VERSION 5.7 ;
DIVIDERCHAR "/" ;
BUSBITCHARS "[]" ;

VERSION 5.7 ;

BUSBITCHARS "[]" ;
DIVIDERCHAR "/" ;

UNITS
  TIME NANOSECONDS 1 ;
  CAPACITANCE PICOFARADS 1 ;
  RESISTANCE OHMS 1 ;
  DATABASE MICRONS 1000 ;
END UNITS

MANUFACTURINGGRID 0.005 ;

PROPERTYDEFINITIONS
  LAYER LEF58_TYPE STRING ;
END PROPERTYDEFINITIONS

# High density, single height
SITE obssite
  SYMMETRY Y ;
  CLASS CORE ;
  SIZE 0.36 BY 6.12 ;
END obssite


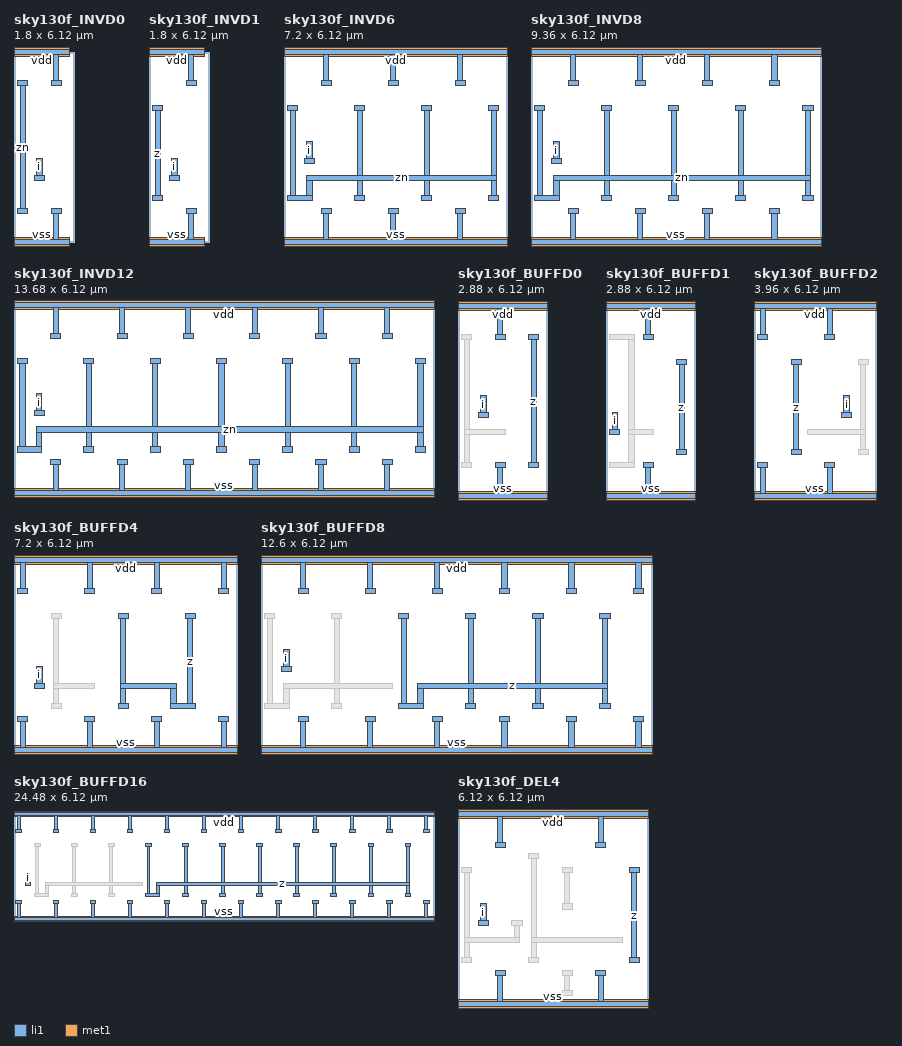
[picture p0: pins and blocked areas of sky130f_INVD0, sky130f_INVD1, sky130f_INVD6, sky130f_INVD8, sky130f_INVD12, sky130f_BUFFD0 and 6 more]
MACRO sky130f_INVD0
  CLASS CORE ;
  FOREIGN sky130f_INVD0 ;
  ORIGIN 0.000 0.000 ;
  SIZE 1.800 BY 6.120 ;
  SYMMETRY X Y R90 ;
  SITE obssite ;
  PIN i
    DIRECTION INPUT ;
    USE SIGNAL ;
    ANTENNAGATEAREA 0.145500 ;
    PORT
      LAYER li1 ;
        RECT 0.655 1.980 0.985 2.150 ;
        RECT 0.735 2.150 0.905 2.690 ;
    END
  END i
  PIN vdd
    DIRECTION INOUT ;
    USE POWER ;
    SHAPE ABUTMENT ;
    PORT
      LAYER li1 ;
        RECT 1.195 5.030 1.525 5.200 ;
        RECT 1.275 5.200 1.445 6.035 ;
        RECT 0.000 6.035 1.800 6.205 ;
      LAYER met1 ;
        RECT 0.000 5.985 1.800 6.255 ;
    END
  END vdd
  PIN vss
    DIRECTION INOUT ;
    USE GROUND ;
    SHAPE ABUTMENT ;
    PORT
      LAYER li1 ;
        RECT 0.000 -0.085 1.800 0.085 ;
        RECT 1.275 0.085 1.445 0.920 ;
        RECT 1.195 0.920 1.525 1.090 ;
      LAYER met1 ;
        RECT 0.000 -0.135 1.800 0.135 ;
    END
  END vss
  PIN zn
    DIRECTION OUTPUT ;
    USE SIGNAL ;
    ANTENNADIFFAREA 0.591700 ;
    PORT
      LAYER li1 ;
        RECT 0.115 0.920 0.445 1.090 ;
        RECT 0.195 1.090 0.365 5.030 ;
        RECT 0.115 5.030 0.445 5.200 ;
    END
  END zn
END sky130f_INVD0

MACRO sky130f_INVD1
  CLASS CORE ;
  FOREIGN sky130f_INVD1 ;
  ORIGIN 0.000 0.000 ;
  SIZE 1.800 BY 6.120 ;
  SYMMETRY X Y R90 ;
  SITE obssite ;
  PIN z
    DIRECTION OUTPUT ;
    USE SIGNAL ;
    ANTENNADIFFAREA 1.098000 ;
    PORT
      LAYER li1 ;
        RECT 0.115 1.330 0.445 1.500 ;
        RECT 0.195 1.500 0.365 4.220 ;
        RECT 0.115 4.220 0.445 4.390 ;
    END
  END z
  PIN vdd
    DIRECTION INOUT ;
    USE POWER ;
    SHAPE ABUTMENT ;
    PORT
      LAYER li1 ;
        RECT 1.195 5.030 1.525 5.200 ;
        RECT 1.275 5.200 1.445 6.035 ;
        RECT 0.000 6.035 1.800 6.205 ;
      LAYER met1 ;
        RECT 0.000 5.985 1.800 6.255 ;
    END
  END vdd
  PIN vss
    DIRECTION INOUT ;
    USE GROUND ;
    SHAPE ABUTMENT ;
    PORT
      LAYER li1 ;
        RECT 0.000 -0.085 1.800 0.085 ;
        RECT 1.275 0.085 1.445 0.920 ;
        RECT 1.195 0.920 1.525 1.090 ;
      LAYER met1 ;
        RECT 0.000 -0.135 1.800 0.135 ;
    END
  END vss
  PIN i
    DIRECTION INPUT ;
    USE SIGNAL ;
    ANTENNAGATEAREA 0.270000 ;
    PORT
      LAYER li1 ;
        RECT 0.655 1.980 0.985 2.150 ;
        RECT 0.735 2.150 0.905 2.690 ;
    END
  END i
END sky130f_INVD1

MACRO sky130f_INVD6
  CLASS CORE ;
  FOREIGN sky130f_INVD6 ;
  ORIGIN 0.000 0.000 ;
  SIZE 7.200 BY 6.120 ;
  SYMMETRY X Y R90 ;
  SITE obssite ;
  PIN i
    DIRECTION INPUT ;
    USE SIGNAL ;
    ANTENNAGATEAREA 1.620000 ;
    PORT
      LAYER li1 ;
        RECT 0.655 2.520 0.985 2.690 ;
        RECT 0.735 2.690 0.905 3.230 ;
    END
  END i
  PIN vdd
    DIRECTION INOUT ;
    USE POWER ;
    SHAPE ABUTMENT ;
    PORT
      LAYER li1 ;
        RECT 1.195 5.030 1.525 5.200 ;
        RECT 3.355 5.030 3.685 5.200 ;
        RECT 5.515 5.030 5.845 5.200 ;
        RECT 1.275 5.200 1.445 6.035 ;
        RECT 3.435 5.200 3.605 6.035 ;
        RECT 5.595 5.200 5.765 6.035 ;
        RECT 0.000 6.035 7.200 6.205 ;
      LAYER met1 ;
        RECT 0.000 5.985 7.200 6.255 ;
    END
  END vdd
  PIN vss
    DIRECTION INOUT ;
    USE GROUND ;
    SHAPE ABUTMENT ;
    PORT
      LAYER li1 ;
        RECT 0.000 -0.085 7.200 0.085 ;
        RECT 1.275 0.085 1.445 0.920 ;
        RECT 3.435 0.085 3.605 0.920 ;
        RECT 5.595 0.085 5.765 0.920 ;
        RECT 1.195 0.920 1.525 1.090 ;
        RECT 3.355 0.920 3.685 1.090 ;
        RECT 5.515 0.920 5.845 1.090 ;
      LAYER met1 ;
        RECT 0.000 -0.135 7.200 0.135 ;
    END
  END vss
  PIN zn
    DIRECTION OUTPUT ;
    USE SIGNAL ;
    ANTENNADIFFAREA 5.544000 ;
    PORT
      LAYER li1 ;
        RECT 0.115 1.330 0.905 1.500 ;
        RECT 2.275 1.330 2.605 1.500 ;
        RECT 4.435 1.330 4.765 1.500 ;
        RECT 6.595 1.330 6.925 1.500 ;
        RECT 0.195 1.500 0.365 4.220 ;
        RECT 0.735 1.500 0.905 1.980 ;
        RECT 2.355 1.500 2.525 1.980 ;
        RECT 4.515 1.500 4.685 1.980 ;
        RECT 6.675 1.500 6.845 1.980 ;
        RECT 0.735 1.980 6.845 2.150 ;
        RECT 2.355 2.150 2.525 4.220 ;
        RECT 4.515 2.150 4.685 4.220 ;
        RECT 6.675 2.150 6.845 4.220 ;
        RECT 0.115 4.220 0.445 4.390 ;
        RECT 2.275 4.220 2.605 4.390 ;
        RECT 4.435 4.220 4.765 4.390 ;
        RECT 6.595 4.220 6.925 4.390 ;
    END
  END zn
END sky130f_INVD6

MACRO sky130f_INVD8
  CLASS CORE ;
  FOREIGN sky130f_INVD8 ;
  ORIGIN 0.000 0.000 ;
  SIZE 9.360 BY 6.120 ;
  SYMMETRY X Y R90 ;
  SITE obssite ;
  PIN i
    DIRECTION INPUT ;
    USE SIGNAL ;
    ANTENNAGATEAREA 2.160000 ;
    PORT
      LAYER li1 ;
        RECT 0.655 2.520 0.985 2.690 ;
        RECT 0.735 2.690 0.905 3.230 ;
    END
  END i
  PIN vdd
    DIRECTION INOUT ;
    USE POWER ;
    SHAPE ABUTMENT ;
    PORT
      LAYER li1 ;
        RECT 1.195 5.030 1.525 5.200 ;
        RECT 3.355 5.030 3.685 5.200 ;
        RECT 5.515 5.030 5.845 5.200 ;
        RECT 7.675 5.030 8.005 5.200 ;
        RECT 1.275 5.200 1.445 6.035 ;
        RECT 3.435 5.200 3.605 6.035 ;
        RECT 5.595 5.200 5.765 6.035 ;
        RECT 7.755 5.200 7.925 6.035 ;
        RECT 0.000 6.035 9.360 6.205 ;
      LAYER met1 ;
        RECT 0.000 5.985 9.360 6.255 ;
    END
  END vdd
  PIN vss
    DIRECTION INOUT ;
    USE GROUND ;
    SHAPE ABUTMENT ;
    PORT
      LAYER li1 ;
        RECT 0.000 -0.085 9.360 0.085 ;
        RECT 1.275 0.085 1.445 0.920 ;
        RECT 3.435 0.085 3.605 0.920 ;
        RECT 5.595 0.085 5.765 0.920 ;
        RECT 7.755 0.085 7.925 0.920 ;
        RECT 1.195 0.920 1.525 1.090 ;
        RECT 3.355 0.920 3.685 1.090 ;
        RECT 5.515 0.920 5.845 1.090 ;
        RECT 7.675 0.920 8.005 1.090 ;
      LAYER met1 ;
        RECT 0.000 -0.135 9.360 0.135 ;
    END
  END vss
  PIN zn
    DIRECTION OUTPUT ;
    USE SIGNAL ;
    ANTENNADIFFAREA 7.218000 ;
    PORT
      LAYER li1 ;
        RECT 0.115 1.330 0.905 1.500 ;
        RECT 2.275 1.330 2.605 1.500 ;
        RECT 4.435 1.330 4.765 1.500 ;
        RECT 6.595 1.330 6.925 1.500 ;
        RECT 8.755 1.330 9.085 1.500 ;
        RECT 0.195 1.500 0.365 4.220 ;
        RECT 0.735 1.500 0.905 1.980 ;
        RECT 2.355 1.500 2.525 1.980 ;
        RECT 4.515 1.500 4.685 1.980 ;
        RECT 6.675 1.500 6.845 1.980 ;
        RECT 8.835 1.500 9.005 1.980 ;
        RECT 0.735 1.980 9.005 2.150 ;
        RECT 2.355 2.150 2.525 4.220 ;
        RECT 4.515 2.150 4.685 4.220 ;
        RECT 6.675 2.150 6.845 4.220 ;
        RECT 8.835 2.150 9.005 4.220 ;
        RECT 0.115 4.220 0.445 4.390 ;
        RECT 2.275 4.220 2.605 4.390 ;
        RECT 4.435 4.220 4.765 4.390 ;
        RECT 6.595 4.220 6.925 4.390 ;
        RECT 8.755 4.220 9.085 4.390 ;
    END
  END zn
END sky130f_INVD8

MACRO sky130f_INVD12
  CLASS CORE ;
  FOREIGN sky130f_INVD12 ;
  ORIGIN 0.000 0.000 ;
  SIZE 13.680 BY 6.120 ;
  SYMMETRY X Y R90 ;
  SITE obssite ;
  PIN i
    DIRECTION INPUT ;
    USE SIGNAL ;
    ANTENNAGATEAREA 3.240000 ;
    PORT
      LAYER li1 ;
        RECT 0.655 2.520 0.985 2.690 ;
        RECT 0.735 2.690 0.905 3.230 ;
    END
  END i
  PIN vdd
    DIRECTION INOUT ;
    USE POWER ;
    SHAPE ABUTMENT ;
    PORT
      LAYER li1 ;
        RECT 1.195 5.030 1.525 5.200 ;
        RECT 3.355 5.030 3.685 5.200 ;
        RECT 5.515 5.030 5.845 5.200 ;
        RECT 7.675 5.030 8.005 5.200 ;
        RECT 9.835 5.030 10.165 5.200 ;
        RECT 11.995 5.030 12.325 5.200 ;
        RECT 1.275 5.200 1.445 6.035 ;
        RECT 3.435 5.200 3.605 6.035 ;
        RECT 5.595 5.200 5.765 6.035 ;
        RECT 7.755 5.200 7.925 6.035 ;
        RECT 9.915 5.200 10.085 6.035 ;
        RECT 12.075 5.200 12.245 6.035 ;
        RECT 0.000 6.035 13.680 6.205 ;
      LAYER met1 ;
        RECT 0.000 5.985 13.680 6.255 ;
    END
  END vdd
  PIN vss
    DIRECTION INOUT ;
    USE GROUND ;
    SHAPE ABUTMENT ;
    PORT
      LAYER li1 ;
        RECT 0.000 -0.085 13.680 0.085 ;
        RECT 1.275 0.085 1.445 0.920 ;
        RECT 3.435 0.085 3.605 0.920 ;
        RECT 5.595 0.085 5.765 0.920 ;
        RECT 7.755 0.085 7.925 0.920 ;
        RECT 9.915 0.085 10.085 0.920 ;
        RECT 12.075 0.085 12.245 0.920 ;
        RECT 1.195 0.920 1.525 1.090 ;
        RECT 3.355 0.920 3.685 1.090 ;
        RECT 5.515 0.920 5.845 1.090 ;
        RECT 7.675 0.920 8.005 1.090 ;
        RECT 9.835 0.920 10.165 1.090 ;
        RECT 11.995 0.920 12.325 1.090 ;
      LAYER met1 ;
        RECT 0.000 -0.135 13.680 0.135 ;
    END
  END vss
  PIN zn
    DIRECTION OUTPUT ;
    USE SIGNAL ;
    ANTENNADIFFAREA 10.566000 ;
    PORT
      LAYER li1 ;
        RECT 0.115 1.330 0.905 1.500 ;
        RECT 2.275 1.330 2.605 1.500 ;
        RECT 4.435 1.330 4.765 1.500 ;
        RECT 6.595 1.330 6.925 1.500 ;
        RECT 8.755 1.330 9.085 1.500 ;
        RECT 10.915 1.330 11.245 1.500 ;
        RECT 13.075 1.330 13.405 1.500 ;
        RECT 0.195 1.500 0.365 4.220 ;
        RECT 0.735 1.500 0.905 1.980 ;
        RECT 2.355 1.500 2.525 1.980 ;
        RECT 4.515 1.500 4.685 1.980 ;
        RECT 6.675 1.500 6.845 1.980 ;
        RECT 8.835 1.500 9.005 1.980 ;
        RECT 10.995 1.500 11.165 1.980 ;
        RECT 13.155 1.500 13.325 1.980 ;
        RECT 0.735 1.980 13.325 2.150 ;
        RECT 2.355 2.150 2.525 4.220 ;
        RECT 4.515 2.150 4.685 4.220 ;
        RECT 6.675 2.150 6.845 4.220 ;
        RECT 8.835 2.150 9.005 4.220 ;
        RECT 10.995 2.150 11.165 4.220 ;
        RECT 13.155 2.150 13.325 4.220 ;
        RECT 0.115 4.220 0.445 4.390 ;
        RECT 2.275 4.220 2.605 4.390 ;
        RECT 4.435 4.220 4.765 4.390 ;
        RECT 6.595 4.220 6.925 4.390 ;
        RECT 8.755 4.220 9.085 4.390 ;
        RECT 10.915 4.220 11.245 4.390 ;
        RECT 13.075 4.220 13.405 4.390 ;
    END
  END zn
END sky130f_INVD12

MACRO sky130f_BUFFD0
  CLASS CORE ;
  FOREIGN sky130f_BUFFD0 ;
  ORIGIN 0.000 0.000 ;
  SIZE 2.880 BY 6.120 ;
  SYMMETRY X Y R90 ;
  SITE obssite ;
  PIN i
    DIRECTION INPUT ;
    USE SIGNAL ;
    ANTENNAGATEAREA 0.126000 ;
    PORT
      LAYER li1 ;
        RECT 0.655 2.520 0.985 2.690 ;
        RECT 0.735 2.690 0.905 3.230 ;
    END
  END i
  PIN vdd
    DIRECTION INOUT ;
    USE POWER ;
    SHAPE ABUTMENT ;
    PORT
      LAYER li1 ;
        RECT 1.195 5.030 1.525 5.200 ;
        RECT 1.275 5.200 1.445 6.035 ;
        RECT 0.000 6.035 2.880 6.205 ;
      LAYER met1 ;
        RECT 0.000 5.985 2.880 6.255 ;
    END
  END vdd
  PIN vss
    DIRECTION INOUT ;
    USE GROUND ;
    SHAPE ABUTMENT ;
    PORT
      LAYER li1 ;
        RECT 0.000 -0.085 2.880 0.085 ;
        RECT 1.275 0.085 1.445 0.920 ;
        RECT 1.195 0.920 1.525 1.090 ;
      LAYER met1 ;
        RECT 0.000 -0.135 2.880 0.135 ;
    END
  END vss
  PIN z
    DIRECTION OUTPUT ;
    USE SIGNAL ;
    ANTENNADIFFAREA 0.582550 ;
    PORT
      LAYER li1 ;
        RECT 2.275 0.920 2.605 1.090 ;
        RECT 2.355 1.090 2.525 5.030 ;
        RECT 2.275 5.030 2.605 5.200 ;
    END
  END z
  OBS
    LAYER li1 ;
      RECT 0.115 0.920 0.445 1.090 ;
      RECT 0.195 1.090 0.365 1.980 ;
      RECT 0.195 1.980 1.525 2.150 ;
      RECT 0.195 2.150 0.365 5.030 ;
      RECT 0.115 5.030 0.445 5.200 ;
  END
END sky130f_BUFFD0

MACRO sky130f_BUFFD1
  CLASS CORE ;
  FOREIGN sky130f_BUFFD1 ;
  ORIGIN 0.000 0.000 ;
  SIZE 2.880 BY 6.120 ;
  SYMMETRY X Y R90 ;
  SITE obssite ;
  PIN i
    DIRECTION INPUT ;
    USE SIGNAL ;
    ANTENNAGATEAREA 0.145500 ;
    PORT
      LAYER li1 ;
        RECT 0.115 1.980 0.445 2.150 ;
        RECT 0.195 2.150 0.365 2.690 ;
    END
  END i
  PIN vdd
    DIRECTION INOUT ;
    USE POWER ;
    SHAPE ABUTMENT ;
    PORT
      LAYER li1 ;
        RECT 1.195 5.030 1.525 5.200 ;
        RECT 1.275 5.200 1.445 6.035 ;
        RECT 0.000 6.035 2.880 6.205 ;
      LAYER met1 ;
        RECT 0.000 5.985 2.880 6.255 ;
    END
  END vdd
  PIN vss
    DIRECTION INOUT ;
    USE GROUND ;
    SHAPE ABUTMENT ;
    PORT
      LAYER li1 ;
        RECT 0.000 -0.085 2.880 0.085 ;
        RECT 1.275 0.085 1.445 0.920 ;
        RECT 1.195 0.920 1.525 1.090 ;
      LAYER met1 ;
        RECT 0.000 -0.135 2.880 0.135 ;
    END
  END vss
  PIN z
    DIRECTION OUTPUT ;
    USE SIGNAL ;
    ANTENNADIFFAREA 1.098000 ;
    PORT
      LAYER li1 ;
        RECT 2.275 1.330 2.605 1.500 ;
        RECT 2.355 1.500 2.525 4.220 ;
        RECT 2.275 4.220 2.605 4.390 ;
    END
  END z
  OBS
    LAYER li1 ;
      RECT 0.115 0.920 0.905 1.090 ;
      RECT 0.735 1.090 0.905 1.980 ;
      RECT 0.735 1.980 1.525 2.150 ;
      RECT 0.735 2.150 0.905 5.030 ;
      RECT 0.115 5.030 0.905 5.200 ;
  END
END sky130f_BUFFD1

MACRO sky130f_BUFFD2
  CLASS CORE ;
  FOREIGN sky130f_BUFFD2 ;
  ORIGIN 0.000 0.000 ;
  SIZE 3.960 BY 6.120 ;
  SYMMETRY X Y R90 ;
  SITE obssite ;
  PIN i
    DIRECTION INPUT ;
    USE SIGNAL ;
    ANTENNAGATEAREA 0.270000 ;
    PORT
      LAYER li1 ;
        RECT 2.815 2.520 3.145 2.690 ;
        RECT 2.895 2.690 3.065 3.230 ;
    END
  END i
  PIN vdd
    DIRECTION INOUT ;
    USE POWER ;
    SHAPE ABUTMENT ;
    PORT
      LAYER li1 ;
        RECT 0.115 5.030 0.445 5.200 ;
        RECT 2.275 5.030 2.605 5.200 ;
        RECT 0.195 5.200 0.365 6.035 ;
        RECT 2.355 5.200 2.525 6.035 ;
        RECT 0.000 6.035 3.960 6.205 ;
      LAYER met1 ;
        RECT 0.000 5.985 3.960 6.255 ;
    END
  END vdd
  PIN vss
    DIRECTION INOUT ;
    USE GROUND ;
    SHAPE ABUTMENT ;
    PORT
      LAYER li1 ;
        RECT 0.000 -0.085 3.960 0.085 ;
        RECT 0.195 0.085 0.365 0.920 ;
        RECT 2.355 0.085 2.525 0.920 ;
        RECT 0.115 0.920 0.445 1.090 ;
        RECT 2.275 0.920 2.605 1.090 ;
      LAYER met1 ;
        RECT 0.000 -0.135 3.960 0.135 ;
    END
  END vss
  PIN z
    DIRECTION OUTPUT ;
    USE SIGNAL ;
    ANTENNADIFFAREA 1.674000 ;
    PORT
      LAYER li1 ;
        RECT 1.195 1.330 1.525 1.500 ;
        RECT 1.275 1.500 1.445 4.220 ;
        RECT 1.195 4.220 1.525 4.390 ;
    END
  END z
  OBS
    LAYER li1 ;
      RECT 3.355 1.330 3.685 1.500 ;
      RECT 3.435 1.500 3.605 1.980 ;
      RECT 1.735 1.980 3.605 2.150 ;
      RECT 3.435 2.150 3.605 4.220 ;
      RECT 3.355 4.220 3.685 4.390 ;
  END
END sky130f_BUFFD2

MACRO sky130f_BUFFD4
  CLASS CORE ;
  FOREIGN sky130f_BUFFD4 ;
  ORIGIN 0.000 0.000 ;
  SIZE 7.200 BY 6.120 ;
  SYMMETRY X Y R90 ;
  SITE obssite ;
  PIN i
    DIRECTION INPUT ;
    USE SIGNAL ;
    ANTENNAGATEAREA 0.540000 ;
    PORT
      LAYER li1 ;
        RECT 0.655 1.980 0.985 2.150 ;
        RECT 0.735 2.150 0.905 2.690 ;
    END
  END i
  PIN vdd
    DIRECTION INOUT ;
    USE POWER ;
    SHAPE ABUTMENT ;
    PORT
      LAYER li1 ;
        RECT 0.115 5.030 0.445 5.200 ;
        RECT 2.275 5.030 2.605 5.200 ;
        RECT 4.435 5.030 4.765 5.200 ;
        RECT 6.595 5.030 6.925 5.200 ;
        RECT 0.195 5.200 0.365 6.035 ;
        RECT 2.355 5.200 2.525 6.035 ;
        RECT 4.515 5.200 4.685 6.035 ;
        RECT 6.675 5.200 6.845 6.035 ;
        RECT 0.000 6.035 7.200 6.205 ;
      LAYER met1 ;
        RECT 0.000 5.985 7.200 6.255 ;
    END
  END vdd
  PIN vss
    DIRECTION INOUT ;
    USE GROUND ;
    SHAPE ABUTMENT ;
    PORT
      LAYER li1 ;
        RECT 0.000 -0.085 7.200 0.085 ;
        RECT 0.195 0.085 0.365 0.920 ;
        RECT 2.355 0.085 2.525 0.920 ;
        RECT 4.515 0.085 4.685 0.920 ;
        RECT 6.675 0.085 6.845 0.920 ;
        RECT 0.115 0.920 0.445 1.090 ;
        RECT 2.275 0.920 2.605 1.090 ;
        RECT 4.435 0.920 4.765 1.090 ;
        RECT 6.595 0.920 6.925 1.090 ;
      LAYER met1 ;
        RECT 0.000 -0.135 7.200 0.135 ;
    END
  END vss
  PIN z
    DIRECTION OUTPUT ;
    USE SIGNAL ;
    ANTENNADIFFAREA 3.348000 ;
    PORT
      LAYER li1 ;
        RECT 3.355 1.330 3.685 1.500 ;
        RECT 5.055 1.330 5.845 1.500 ;
        RECT 3.435 1.500 3.605 1.980 ;
        RECT 5.055 1.500 5.225 1.980 ;
        RECT 5.595 1.500 5.765 4.220 ;
        RECT 3.435 1.980 5.225 2.150 ;
        RECT 3.435 2.150 3.605 4.220 ;
        RECT 3.355 4.220 3.685 4.390 ;
        RECT 5.515 4.220 5.845 4.390 ;
    END
  END z
  OBS
    LAYER li1 ;
      RECT 1.195 1.330 1.525 1.500 ;
      RECT 1.275 1.500 1.445 1.980 ;
      RECT 1.275 1.980 2.605 2.150 ;
      RECT 1.275 2.150 1.445 4.220 ;
      RECT 1.195 4.220 1.525 4.390 ;
  END
END sky130f_BUFFD4

MACRO sky130f_BUFFD8
  CLASS CORE ;
  FOREIGN sky130f_BUFFD8 ;
  ORIGIN 0.000 0.000 ;
  SIZE 12.600 BY 6.120 ;
  SYMMETRY X Y R90 ;
  SITE obssite ;
  PIN i
    DIRECTION INPUT ;
    USE SIGNAL ;
    ANTENNAGATEAREA 0.720750 ;
    PORT
      LAYER li1 ;
        RECT 0.655 2.520 0.985 2.690 ;
        RECT 0.735 2.690 0.905 3.230 ;
    END
  END i
  PIN vdd
    DIRECTION INOUT ;
    USE POWER ;
    SHAPE ABUTMENT ;
    PORT
      LAYER li1 ;
        RECT 1.195 5.030 1.525 5.200 ;
        RECT 3.355 5.030 3.685 5.200 ;
        RECT 5.515 5.030 5.845 5.200 ;
        RECT 7.675 5.030 8.005 5.200 ;
        RECT 9.835 5.030 10.165 5.200 ;
        RECT 11.995 5.030 12.325 5.200 ;
        RECT 1.275 5.200 1.445 6.035 ;
        RECT 3.435 5.200 3.605 6.035 ;
        RECT 5.595 5.200 5.765 6.035 ;
        RECT 7.755 5.200 7.925 6.035 ;
        RECT 9.915 5.200 10.085 6.035 ;
        RECT 12.075 5.200 12.245 6.035 ;
        RECT 0.000 6.035 12.600 6.205 ;
      LAYER met1 ;
        RECT 0.000 5.985 12.600 6.255 ;
    END
  END vdd
  PIN vss
    DIRECTION INOUT ;
    USE GROUND ;
    SHAPE ABUTMENT ;
    PORT
      LAYER li1 ;
        RECT 0.000 -0.085 12.600 0.085 ;
        RECT 1.275 0.085 1.445 0.920 ;
        RECT 3.435 0.085 3.605 0.920 ;
        RECT 5.595 0.085 5.765 0.920 ;
        RECT 7.755 0.085 7.925 0.920 ;
        RECT 9.915 0.085 10.085 0.920 ;
        RECT 12.075 0.085 12.245 0.920 ;
        RECT 1.195 0.920 1.525 1.090 ;
        RECT 3.355 0.920 3.685 1.090 ;
        RECT 5.515 0.920 5.845 1.090 ;
        RECT 7.675 0.920 8.005 1.090 ;
        RECT 9.835 0.920 10.165 1.090 ;
        RECT 11.995 0.920 12.325 1.090 ;
      LAYER met1 ;
        RECT 0.000 -0.135 12.600 0.135 ;
    END
  END vss
  PIN z
    DIRECTION OUTPUT ;
    USE SIGNAL ;
    ANTENNADIFFAREA 6.696000 ;
    PORT
      LAYER li1 ;
        RECT 4.435 1.330 5.225 1.500 ;
        RECT 6.595 1.330 6.925 1.500 ;
        RECT 8.755 1.330 9.085 1.500 ;
        RECT 10.915 1.330 11.245 1.500 ;
        RECT 4.515 1.500 4.685 4.220 ;
        RECT 5.055 1.500 5.225 1.980 ;
        RECT 6.675 1.500 6.845 1.980 ;
        RECT 8.835 1.500 9.005 1.980 ;
        RECT 10.995 1.500 11.165 1.980 ;
        RECT 5.055 1.980 11.165 2.150 ;
        RECT 6.675 2.150 6.845 4.220 ;
        RECT 8.835 2.150 9.005 4.220 ;
        RECT 10.995 2.150 11.165 4.220 ;
        RECT 4.435 4.220 4.765 4.390 ;
        RECT 6.595 4.220 6.925 4.390 ;
        RECT 8.755 4.220 9.085 4.390 ;
        RECT 10.915 4.220 11.245 4.390 ;
    END
  END z
  OBS
    LAYER li1 ;
      RECT 0.115 1.330 0.905 1.500 ;
      RECT 2.275 1.330 2.605 1.500 ;
      RECT 0.195 1.500 0.365 4.220 ;
      RECT 0.735 1.500 0.905 1.980 ;
      RECT 2.355 1.500 2.525 1.980 ;
      RECT 0.735 1.980 4.225 2.150 ;
      RECT 2.355 2.150 2.525 4.220 ;
      RECT 0.115 4.220 0.445 4.390 ;
      RECT 2.275 4.220 2.605 4.390 ;
  END
END sky130f_BUFFD8

MACRO sky130f_BUFFD16
  CLASS CORE ;
  FOREIGN sky130f_BUFFD16 ;
  ORIGIN 0.000 0.000 ;
  SIZE 24.480 BY 6.120 ;
  SYMMETRY X Y R90 ;
  SITE obssite ;
  PIN i
    DIRECTION INPUT ;
    USE SIGNAL ;
    ANTENNAGATEAREA 1.476000 ;
    PORT
      LAYER li1 ;
        RECT 0.655 1.980 0.985 2.150 ;
        RECT 0.735 2.150 0.905 2.690 ;
    END
  END i
  PIN vdd
    DIRECTION INOUT ;
    USE POWER ;
    SHAPE ABUTMENT ;
    PORT
      LAYER li1 ;
        RECT 0.115 5.030 0.445 5.200 ;
        RECT 2.275 5.030 2.605 5.200 ;
        RECT 4.435 5.030 4.765 5.200 ;
        RECT 6.595 5.030 6.925 5.200 ;
        RECT 8.755 5.030 9.085 5.200 ;
        RECT 10.915 5.030 11.245 5.200 ;
        RECT 13.075 5.030 13.405 5.200 ;
        RECT 15.235 5.030 15.565 5.200 ;
        RECT 17.395 5.030 17.725 5.200 ;
        RECT 19.555 5.030 19.885 5.200 ;
        RECT 21.715 5.030 22.045 5.200 ;
        RECT 23.875 5.030 24.205 5.200 ;
        RECT 0.195 5.200 0.365 6.035 ;
        RECT 2.355 5.200 2.525 6.035 ;
        RECT 4.515 5.200 4.685 6.035 ;
        RECT 6.675 5.200 6.845 6.035 ;
        RECT 8.835 5.200 9.005 6.035 ;
        RECT 10.995 5.200 11.165 6.035 ;
        RECT 13.155 5.200 13.325 6.035 ;
        RECT 15.315 5.200 15.485 6.035 ;
        RECT 17.475 5.200 17.645 6.035 ;
        RECT 19.635 5.200 19.805 6.035 ;
        RECT 21.795 5.200 21.965 6.035 ;
        RECT 23.955 5.200 24.125 6.035 ;
        RECT 0.000 6.035 24.480 6.205 ;
      LAYER met1 ;
        RECT 0.000 5.985 24.480 6.255 ;
    END
  END vdd
  PIN vss
    DIRECTION INOUT ;
    USE GROUND ;
    SHAPE ABUTMENT ;
    PORT
      LAYER li1 ;
        RECT 0.000 -0.085 24.480 0.085 ;
        RECT 0.195 0.085 0.365 0.920 ;
        RECT 2.355 0.085 2.525 0.920 ;
        RECT 4.515 0.085 4.685 0.920 ;
        RECT 6.675 0.085 6.845 0.920 ;
        RECT 8.835 0.085 9.005 0.920 ;
        RECT 10.995 0.085 11.165 0.920 ;
        RECT 13.155 0.085 13.325 0.920 ;
        RECT 15.315 0.085 15.485 0.920 ;
        RECT 17.475 0.085 17.645 0.920 ;
        RECT 19.635 0.085 19.805 0.920 ;
        RECT 21.795 0.085 21.965 0.920 ;
        RECT 23.955 0.085 24.125 0.920 ;
        RECT 0.115 0.920 0.445 1.090 ;
        RECT 2.275 0.920 2.605 1.090 ;
        RECT 4.435 0.920 4.765 1.090 ;
        RECT 6.595 0.920 6.925 1.090 ;
        RECT 8.755 0.920 9.085 1.090 ;
        RECT 10.915 0.920 11.245 1.090 ;
        RECT 13.075 0.920 13.405 1.090 ;
        RECT 15.235 0.920 15.565 1.090 ;
        RECT 17.395 0.920 17.725 1.090 ;
        RECT 19.555 0.920 19.885 1.090 ;
        RECT 21.715 0.920 22.045 1.090 ;
        RECT 23.875 0.920 24.205 1.090 ;
      LAYER met1 ;
        RECT 0.000 -0.135 24.480 0.135 ;
    END
  END vss
  PIN z
    DIRECTION OUTPUT ;
    USE SIGNAL ;
    ANTENNADIFFAREA 13.392000 ;
    PORT
      LAYER li1 ;
        RECT 7.675 1.330 8.465 1.500 ;
        RECT 9.835 1.330 10.165 1.500 ;
        RECT 11.995 1.330 12.325 1.500 ;
        RECT 14.155 1.330 14.485 1.500 ;
        RECT 16.315 1.330 16.645 1.500 ;
        RECT 18.475 1.330 18.805 1.500 ;
        RECT 20.635 1.330 20.965 1.500 ;
        RECT 22.795 1.330 23.125 1.500 ;
        RECT 7.755 1.500 7.925 4.220 ;
        RECT 8.295 1.500 8.465 1.980 ;
        RECT 9.915 1.500 10.085 1.980 ;
        RECT 12.075 1.500 12.245 1.980 ;
        RECT 14.235 1.500 14.405 1.980 ;
        RECT 16.395 1.500 16.565 1.980 ;
        RECT 18.555 1.500 18.725 1.980 ;
        RECT 20.715 1.500 20.885 1.980 ;
        RECT 22.875 1.500 23.045 1.980 ;
        RECT 8.295 1.980 23.045 2.150 ;
        RECT 9.915 2.150 10.085 4.220 ;
        RECT 12.075 2.150 12.245 4.220 ;
        RECT 14.235 2.150 14.405 4.220 ;
        RECT 16.395 2.150 16.565 4.220 ;
        RECT 18.555 2.150 18.725 4.220 ;
        RECT 20.715 2.150 20.885 4.220 ;
        RECT 22.875 2.150 23.045 4.220 ;
        RECT 7.675 4.220 8.005 4.390 ;
        RECT 9.835 4.220 10.165 4.390 ;
        RECT 11.995 4.220 12.325 4.390 ;
        RECT 14.155 4.220 14.485 4.390 ;
        RECT 16.315 4.220 16.645 4.390 ;
        RECT 18.475 4.220 18.805 4.390 ;
        RECT 20.635 4.220 20.965 4.390 ;
        RECT 22.795 4.220 23.125 4.390 ;
    END
  END z
  OBS
    LAYER li1 ;
      RECT 1.195 1.330 1.985 1.500 ;
      RECT 3.355 1.330 3.685 1.500 ;
      RECT 5.515 1.330 5.845 1.500 ;
      RECT 1.275 1.500 1.445 4.220 ;
      RECT 1.815 1.500 1.985 1.980 ;
      RECT 3.435 1.500 3.605 1.980 ;
      RECT 5.595 1.500 5.765 1.980 ;
      RECT 1.815 1.980 7.465 2.150 ;
      RECT 3.435 2.150 3.605 4.220 ;
      RECT 5.595 2.150 5.765 4.220 ;
      RECT 1.195 4.220 1.525 4.390 ;
      RECT 3.355 4.220 3.685 4.390 ;
      RECT 5.515 4.220 5.845 4.390 ;
  END
END sky130f_BUFFD16

MACRO sky130f_DEL4
  CLASS CORE ;
  FOREIGN sky130f_DEL4 ;
  ORIGIN 0.000 0.000 ;
  SIZE 6.120 BY 6.120 ;
  SYMMETRY X Y R90 ;
  SITE obssite ;
  PIN i
    DIRECTION INPUT ;
    USE SIGNAL ;
    ANTENNAGATEAREA 0.270000 ;
    PORT
      LAYER li1 ;
        RECT 0.655 2.520 0.985 2.690 ;
        RECT 0.735 2.690 0.905 3.230 ;
    END
  END i
  PIN vdd
    DIRECTION INOUT ;
    USE POWER ;
    SHAPE ABUTMENT ;
    PORT
      LAYER li1 ;
        RECT 1.195 5.030 1.525 5.200 ;
        RECT 4.435 5.030 4.765 5.200 ;
        RECT 1.275 5.200 1.445 6.035 ;
        RECT 4.515 5.200 4.685 6.035 ;
        RECT 0.000 6.035 6.120 6.205 ;
      LAYER met1 ;
        RECT 0.000 5.985 6.120 6.255 ;
    END
  END vdd
  PIN vss
    DIRECTION INOUT ;
    USE GROUND ;
    SHAPE ABUTMENT ;
    PORT
      LAYER li1 ;
        RECT 0.000 -0.085 6.120 0.085 ;
        RECT 1.275 0.085 1.445 0.920 ;
        RECT 4.515 0.085 4.685 0.920 ;
        RECT 1.195 0.920 1.525 1.090 ;
        RECT 4.435 0.920 4.765 1.090 ;
      LAYER met1 ;
        RECT 0.000 -0.135 6.120 0.135 ;
    END
  END vss
  PIN z
    DIRECTION OUTPUT ;
    USE SIGNAL ;
    ANTENNADIFFAREA 1.098000 ;
    PORT
      LAYER li1 ;
        RECT 5.515 1.330 5.845 1.500 ;
        RECT 5.595 1.500 5.765 4.220 ;
        RECT 5.515 4.220 5.845 4.390 ;
    END
  END z
  OBS
    LAYER li1 ;
      RECT 3.355 0.270 3.685 0.440 ;
      RECT 3.435 0.440 3.605 0.920 ;
      RECT 3.355 0.920 3.685 1.090 ;
      RECT 0.115 1.330 0.445 1.500 ;
      RECT 2.275 1.330 2.605 1.500 ;
      RECT 0.195 1.500 0.365 1.980 ;
      RECT 2.355 1.500 2.525 1.980 ;
      RECT 0.195 1.980 1.985 2.150 ;
      RECT 2.355 1.980 5.305 2.150 ;
      RECT 0.195 2.150 0.365 4.220 ;
      RECT 1.815 2.150 1.985 2.520 ;
      RECT 2.355 2.150 2.525 4.690 ;
      RECT 1.735 2.520 2.065 2.690 ;
      RECT 3.355 3.060 3.685 3.230 ;
      RECT 3.435 3.230 3.605 4.220 ;
      RECT 0.115 4.220 0.445 4.390 ;
      RECT 3.355 4.220 3.685 4.390 ;
      RECT 2.275 4.690 2.605 4.860 ;
  END
END sky130f_DEL4

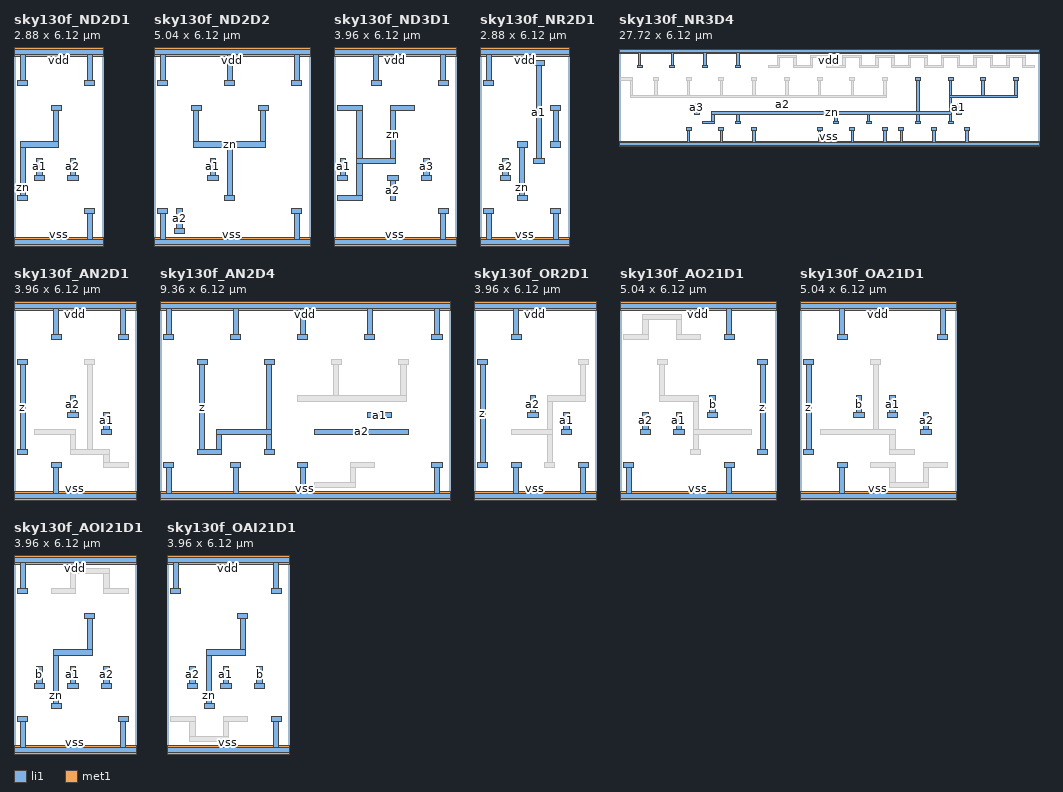
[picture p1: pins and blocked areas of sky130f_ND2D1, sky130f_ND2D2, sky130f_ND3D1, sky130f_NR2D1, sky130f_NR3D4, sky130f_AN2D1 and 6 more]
MACRO sky130f_ND2D1
  CLASS CORE ;
  FOREIGN sky130f_ND2D1 ;
  ORIGIN 0.000 0.000 ;
  SIZE 2.880 BY 6.120 ;
  SYMMETRY X Y R90 ;
  SITE obssite ;
  PIN a1
    DIRECTION INPUT ;
    USE SIGNAL ;
    ANTENNAGATEAREA 0.270000 ;
    PORT
      LAYER li1 ;
        RECT 0.655 1.980 0.985 2.150 ;
        RECT 0.735 2.150 0.905 2.690 ;
    END
  END a1
  PIN a2
    DIRECTION INPUT ;
    USE SIGNAL ;
    ANTENNAGATEAREA 0.270000 ;
    PORT
      LAYER li1 ;
        RECT 1.735 1.980 2.065 2.150 ;
        RECT 1.815 2.150 1.985 2.690 ;
    END
  END a2
  PIN vdd
    DIRECTION INOUT ;
    USE POWER ;
    SHAPE ABUTMENT ;
    PORT
      LAYER li1 ;
        RECT 0.115 5.030 0.445 5.200 ;
        RECT 2.275 5.030 2.605 5.200 ;
        RECT 0.195 5.200 0.365 6.035 ;
        RECT 2.355 5.200 2.525 6.035 ;
        RECT 0.000 6.035 2.880 6.205 ;
      LAYER met1 ;
        RECT 0.000 5.985 2.880 6.255 ;
    END
  END vdd
  PIN vss
    DIRECTION INOUT ;
    USE GROUND ;
    SHAPE ABUTMENT ;
    PORT
      LAYER li1 ;
        RECT 0.000 -0.085 2.880 0.085 ;
        RECT 2.355 0.085 2.525 0.920 ;
        RECT 2.275 0.920 2.605 1.090 ;
      LAYER met1 ;
        RECT 0.000 -0.135 2.880 0.135 ;
    END
  END vss
  PIN zn
    DIRECTION OUTPUT ;
    USE SIGNAL ;
    ANTENNADIFFAREA 1.450000 ;
    PORT
      LAYER li1 ;
        RECT 0.115 1.330 0.445 1.500 ;
        RECT 0.195 1.500 0.365 3.060 ;
        RECT 0.195 3.060 1.445 3.230 ;
        RECT 1.275 3.230 1.445 4.220 ;
        RECT 1.195 4.220 1.525 4.390 ;
    END
  END zn
END sky130f_ND2D1

MACRO sky130f_ND2D2
  CLASS CORE ;
  FOREIGN sky130f_ND2D2 ;
  ORIGIN 0.000 0.000 ;
  SIZE 5.040 BY 6.120 ;
  SYMMETRY X Y R90 ;
  SITE obssite ;
  PIN a1
    DIRECTION INPUT ;
    USE SIGNAL ;
    ANTENNAGATEAREA 0.540000 ;
    PORT
      LAYER li1 ;
        RECT 1.735 1.980 2.065 2.150 ;
        RECT 1.815 2.150 1.985 2.690 ;
    END
  END a1
  PIN a2
    DIRECTION INPUT ;
    USE SIGNAL ;
    ANTENNAGATEAREA 0.540000 ;
    PORT
      LAYER li1 ;
        RECT 0.655 0.270 0.985 0.440 ;
        RECT 0.735 0.440 0.905 1.090 ;
    END
  END a2
  PIN vdd
    DIRECTION INOUT ;
    USE POWER ;
    SHAPE ABUTMENT ;
    PORT
      LAYER li1 ;
        RECT 0.115 5.030 0.445 5.200 ;
        RECT 2.275 5.030 2.605 5.200 ;
        RECT 4.435 5.030 4.765 5.200 ;
        RECT 0.195 5.200 0.365 6.035 ;
        RECT 2.355 5.200 2.525 6.035 ;
        RECT 4.515 5.200 4.685 6.035 ;
        RECT 0.000 6.035 5.040 6.205 ;
      LAYER met1 ;
        RECT 0.000 5.985 5.040 6.255 ;
    END
  END vdd
  PIN vss
    DIRECTION INOUT ;
    USE GROUND ;
    SHAPE ABUTMENT ;
    PORT
      LAYER li1 ;
        RECT 0.000 -0.085 5.040 0.085 ;
        RECT 0.195 0.085 0.365 0.920 ;
        RECT 4.515 0.085 4.685 0.920 ;
        RECT 0.115 0.920 0.445 1.090 ;
        RECT 4.435 0.920 4.765 1.090 ;
      LAYER met1 ;
        RECT 0.000 -0.135 5.040 0.135 ;
    END
  END vss
  PIN zn
    DIRECTION OUTPUT ;
    USE SIGNAL ;
    ANTENNADIFFAREA 2.697000 ;
    PORT
      LAYER li1 ;
        RECT 2.275 1.330 2.605 1.500 ;
        RECT 2.355 1.500 2.525 3.060 ;
        RECT 1.275 3.060 3.605 3.230 ;
        RECT 1.275 3.230 1.445 4.220 ;
        RECT 3.435 3.230 3.605 4.220 ;
        RECT 1.195 4.220 1.525 4.390 ;
        RECT 3.355 4.220 3.685 4.390 ;
    END
  END zn
END sky130f_ND2D2

MACRO sky130f_ND3D1
  CLASS CORE ;
  FOREIGN sky130f_ND3D1 ;
  ORIGIN 0.000 0.000 ;
  SIZE 3.960 BY 6.120 ;
  SYMMETRY X Y R90 ;
  SITE obssite ;
  PIN a1
    DIRECTION INPUT ;
    USE SIGNAL ;
    ANTENNAGATEAREA 0.270000 ;
    PORT
      LAYER li1 ;
        RECT 0.115 1.980 0.445 2.150 ;
        RECT 0.195 2.150 0.365 2.690 ;
    END
  END a1
  PIN a2
    DIRECTION INPUT ;
    USE SIGNAL ;
    ANTENNAGATEAREA 0.270000 ;
    PORT
      LAYER li1 ;
        RECT 1.815 1.330 1.985 1.980 ;
        RECT 1.735 1.980 2.065 2.150 ;
    END
  END a2
  PIN a3
    DIRECTION INPUT ;
    USE SIGNAL ;
    ANTENNAGATEAREA 0.270000 ;
    PORT
      LAYER li1 ;
        RECT 2.815 1.980 3.145 2.150 ;
        RECT 2.895 2.150 3.065 2.690 ;
    END
  END a3
  PIN vdd
    DIRECTION INOUT ;
    USE POWER ;
    SHAPE ABUTMENT ;
    PORT
      LAYER li1 ;
        RECT 1.195 5.030 1.525 5.200 ;
        RECT 3.355 5.030 3.685 5.200 ;
        RECT 1.275 5.200 1.445 6.035 ;
        RECT 3.435 5.200 3.605 6.035 ;
        RECT 0.000 6.035 3.960 6.205 ;
      LAYER met1 ;
        RECT 0.000 5.985 3.960 6.255 ;
    END
  END vdd
  PIN vss
    DIRECTION INOUT ;
    USE GROUND ;
    SHAPE ABUTMENT ;
    PORT
      LAYER li1 ;
        RECT 0.000 -0.085 3.960 0.085 ;
        RECT 3.435 0.085 3.605 0.920 ;
        RECT 3.355 0.920 3.685 1.090 ;
      LAYER met1 ;
        RECT 0.000 -0.135 3.960 0.135 ;
    END
  END vss
  PIN zn
    DIRECTION OUTPUT ;
    USE SIGNAL ;
    ANTENNADIFFAREA 2.121000 ;
    PORT
      LAYER li1 ;
        RECT 0.115 1.330 0.905 1.500 ;
        RECT 0.735 1.500 0.905 2.520 ;
        RECT 0.735 2.520 1.985 2.690 ;
        RECT 0.735 2.690 0.905 4.220 ;
        RECT 1.815 2.690 1.985 4.220 ;
        RECT 0.115 4.220 0.905 4.390 ;
        RECT 1.815 4.220 2.605 4.390 ;
    END
  END zn
END sky130f_ND3D1

MACRO sky130f_NR2D1
  CLASS CORE ;
  FOREIGN sky130f_NR2D1 ;
  ORIGIN 0.000 0.000 ;
  SIZE 2.880 BY 6.120 ;
  SYMMETRY X Y R90 ;
  SITE obssite ;
  PIN a1
    DIRECTION INPUT ;
    USE SIGNAL ;
    ANTENNAGATEAREA 0.270000 ;
    PORT
      LAYER li1 ;
        RECT 1.735 2.520 2.065 2.690 ;
        RECT 1.815 2.690 1.985 5.680 ;
        RECT 1.735 5.680 2.065 5.850 ;
    END
  END a1
  PIN a2
    DIRECTION INPUT ;
    USE SIGNAL ;
    ANTENNAGATEAREA 0.270000 ;
    PORT
      LAYER li1 ;
        RECT 0.655 1.980 0.985 2.150 ;
        RECT 0.735 2.150 0.905 2.690 ;
    END
  END a2
  PIN vdd
    DIRECTION INOUT ;
    USE POWER ;
    SHAPE ABUTMENT ;
    PORT
      LAYER li1 ;
        RECT 0.115 5.030 0.445 5.200 ;
        RECT 0.195 5.200 0.365 6.035 ;
        RECT 0.000 6.035 2.880 6.205 ;
      LAYER met1 ;
        RECT 0.000 5.985 2.880 6.255 ;
    END
  END vdd
  PIN vss
    DIRECTION INOUT ;
    USE GROUND ;
    SHAPE ABUTMENT ;
    PORT
      LAYER li1 ;
        RECT 0.000 -0.085 2.880 0.085 ;
        RECT 0.195 0.085 0.365 0.920 ;
        RECT 2.355 0.085 2.525 0.920 ;
        RECT 0.115 0.920 0.445 1.090 ;
        RECT 2.275 0.920 2.605 1.090 ;
      LAYER met1 ;
        RECT 0.000 -0.135 2.880 0.135 ;
    END
  END vss
  PIN zn
    DIRECTION OUTPUT ;
    USE SIGNAL ;
    ANTENNADIFFAREA 1.322000 ;
    PORT
      LAYER li1 ;
        RECT 1.195 1.330 1.525 1.500 ;
        RECT 1.275 1.500 1.445 3.060 ;
        RECT 1.195 3.060 1.525 3.230 ;
        RECT 2.275 3.060 2.605 3.230 ;
        RECT 2.355 3.230 2.525 4.220 ;
        RECT 2.275 4.220 2.605 4.390 ;
    END
  END zn
END sky130f_NR2D1

MACRO sky130f_NR3D4
  CLASS CORE ;
  FOREIGN sky130f_NR3D4 ;
  ORIGIN 0.000 0.000 ;
  SIZE 27.720 BY 6.120 ;
  SYMMETRY X Y R90 ;
  SITE obssite ;
  PIN a1
    DIRECTION INPUT ;
    USE SIGNAL ;
    ANTENNAGATEAREA 1.740000 ;
    PORT
      LAYER li1 ;
        RECT 22.255 1.980 22.585 2.150 ;
        RECT 22.335 2.150 22.505 2.690 ;
    END
  END a1
  PIN a2
    DIRECTION INPUT ;
    USE SIGNAL ;
    ANTENNAGATEAREA 1.740000 ;
    PORT
      LAYER li1 ;
        RECT 10.375 2.520 11.165 2.690 ;
    END
  END a2
  PIN a3
    DIRECTION INPUT ;
    USE SIGNAL ;
    ANTENNAGATEAREA 1.740000 ;
    PORT
      LAYER li1 ;
        RECT 4.975 1.980 5.305 2.150 ;
        RECT 5.055 2.150 5.225 2.690 ;
    END
  END a3
  PIN vdd
    DIRECTION INOUT ;
    USE POWER ;
    SHAPE ABUTMENT ;
    PORT
      LAYER li1 ;
        RECT 1.195 5.030 1.525 5.200 ;
        RECT 3.355 5.030 3.685 5.200 ;
        RECT 5.515 5.030 5.845 5.200 ;
        RECT 7.675 5.030 8.005 5.200 ;
        RECT 1.275 5.200 1.445 6.035 ;
        RECT 3.435 5.200 3.605 6.035 ;
        RECT 5.595 5.200 5.765 6.035 ;
        RECT 7.755 5.200 7.925 6.035 ;
        RECT 0.000 6.035 27.720 6.205 ;
      LAYER met1 ;
        RECT 0.000 5.985 27.720 6.255 ;
    END
  END vdd
  PIN vss
    DIRECTION INOUT ;
    USE GROUND ;
    SHAPE ABUTMENT ;
    PORT
      LAYER li1 ;
        RECT 0.000 -0.085 27.720 0.085 ;
        RECT 4.515 0.085 4.685 0.920 ;
        RECT 6.675 0.085 6.845 0.920 ;
        RECT 8.835 0.085 9.005 0.920 ;
        RECT 13.155 0.085 13.325 0.920 ;
        RECT 15.315 0.085 15.485 0.920 ;
        RECT 17.475 0.085 17.645 0.920 ;
        RECT 18.555 0.085 18.725 0.920 ;
        RECT 20.715 0.085 20.885 0.920 ;
        RECT 22.875 0.085 23.045 0.920 ;
        RECT 4.435 0.920 4.765 1.090 ;
        RECT 6.595 0.920 6.925 1.090 ;
        RECT 8.755 0.920 9.085 1.090 ;
        RECT 13.075 0.920 13.405 1.090 ;
        RECT 15.235 0.920 15.565 1.090 ;
        RECT 17.395 0.920 17.725 1.090 ;
        RECT 18.475 0.920 18.805 1.090 ;
        RECT 20.635 0.920 20.965 1.090 ;
        RECT 22.795 0.920 23.125 1.090 ;
      LAYER met1 ;
        RECT 0.000 -0.135 27.720 0.135 ;
    END
  END vss
  PIN zn
    DIRECTION OUTPUT ;
    USE SIGNAL ;
    ANTENNADIFFAREA 7.998000 ;
    PORT
      LAYER li1 ;
        RECT 5.515 1.330 6.305 1.500 ;
        RECT 7.675 1.330 8.005 1.500 ;
        RECT 14.155 1.330 14.485 1.500 ;
        RECT 16.315 1.330 16.645 1.500 ;
        RECT 19.555 1.330 19.885 1.500 ;
        RECT 21.715 1.330 22.045 1.500 ;
        RECT 6.135 1.500 6.305 1.980 ;
        RECT 7.755 1.500 7.925 1.980 ;
        RECT 14.235 1.500 14.405 1.980 ;
        RECT 16.395 1.500 16.565 1.980 ;
        RECT 19.635 1.500 19.805 1.980 ;
        RECT 21.795 1.500 21.965 1.980 ;
        RECT 6.135 1.980 21.965 2.150 ;
        RECT 19.635 2.150 19.805 4.220 ;
        RECT 21.795 2.150 21.965 3.060 ;
        RECT 21.795 3.060 26.285 3.230 ;
        RECT 21.795 3.230 21.965 4.220 ;
        RECT 23.955 3.230 24.125 4.220 ;
        RECT 26.115 3.230 26.285 4.220 ;
        RECT 19.555 4.220 19.885 4.390 ;
        RECT 21.715 4.220 22.045 4.390 ;
        RECT 23.875 4.220 24.205 4.390 ;
        RECT 26.035 4.220 26.365 4.390 ;
    END
  END zn
  OBS
    LAYER li1 ;
      RECT 0.735 3.060 17.645 3.230 ;
      RECT 0.735 3.230 0.905 4.220 ;
      RECT 2.355 3.230 2.525 4.220 ;
      RECT 4.515 3.230 4.685 4.220 ;
      RECT 6.675 3.230 6.845 4.220 ;
      RECT 8.835 3.230 9.005 4.220 ;
      RECT 10.995 3.230 11.165 4.220 ;
      RECT 13.155 3.230 13.325 4.220 ;
      RECT 15.315 3.230 15.485 4.220 ;
      RECT 17.475 3.230 17.645 4.220 ;
      RECT 0.115 4.220 0.905 4.390 ;
      RECT 2.275 4.220 2.605 4.390 ;
      RECT 4.435 4.220 4.765 4.390 ;
      RECT 6.595 4.220 6.925 4.390 ;
      RECT 8.755 4.220 9.085 4.390 ;
      RECT 10.915 4.220 11.245 4.390 ;
      RECT 13.075 4.220 13.405 4.390 ;
      RECT 15.235 4.220 15.565 4.390 ;
      RECT 17.395 4.220 17.725 4.390 ;
      RECT 9.835 5.030 10.625 5.200 ;
      RECT 11.535 5.030 12.785 5.200 ;
      RECT 13.695 5.030 14.945 5.200 ;
      RECT 15.855 5.030 17.105 5.200 ;
      RECT 18.015 5.030 19.265 5.200 ;
      RECT 20.175 5.030 21.425 5.200 ;
      RECT 22.335 5.030 23.585 5.200 ;
      RECT 24.495 5.030 25.745 5.200 ;
      RECT 26.655 5.030 27.445 5.200 ;
      RECT 10.455 5.200 10.625 5.680 ;
      RECT 11.535 5.200 11.705 5.680 ;
      RECT 12.615 5.200 12.785 5.680 ;
      RECT 13.695 5.200 13.865 5.680 ;
      RECT 14.775 5.200 14.945 5.680 ;
      RECT 15.855 5.200 16.025 5.680 ;
      RECT 16.935 5.200 17.105 5.680 ;
      RECT 18.015 5.200 18.185 5.680 ;
      RECT 19.095 5.200 19.265 5.680 ;
      RECT 20.175 5.200 20.345 5.680 ;
      RECT 21.255 5.200 21.425 5.680 ;
      RECT 22.335 5.200 22.505 5.680 ;
      RECT 23.415 5.200 23.585 5.680 ;
      RECT 24.495 5.200 24.665 5.680 ;
      RECT 25.575 5.200 25.745 5.680 ;
      RECT 26.655 5.200 26.825 5.680 ;
      RECT 10.455 5.680 11.705 5.850 ;
      RECT 12.615 5.680 13.865 5.850 ;
      RECT 14.775 5.680 16.025 5.850 ;
      RECT 16.935 5.680 18.185 5.850 ;
      RECT 19.095 5.680 20.345 5.850 ;
      RECT 21.255 5.680 22.505 5.850 ;
      RECT 23.415 5.680 24.665 5.850 ;
      RECT 25.575 5.680 26.825 5.850 ;
  END
END sky130f_NR3D4

MACRO sky130f_AN2D1
  CLASS CORE ;
  FOREIGN sky130f_AN2D1 ;
  ORIGIN 0.000 0.000 ;
  SIZE 3.960 BY 6.120 ;
  SYMMETRY X Y R90 ;
  SITE obssite ;
  PIN a1
    DIRECTION INPUT ;
    USE SIGNAL ;
    ANTENNAGATEAREA 0.260250 ;
    PORT
      LAYER li1 ;
        RECT 2.815 1.980 3.145 2.150 ;
        RECT 2.895 2.150 3.065 2.690 ;
    END
  END a1
  PIN a2
    DIRECTION INPUT ;
    USE SIGNAL ;
    ANTENNAGATEAREA 0.260250 ;
    PORT
      LAYER li1 ;
        RECT 1.735 2.520 2.065 2.690 ;
        RECT 1.815 2.690 1.985 3.230 ;
    END
  END a2
  PIN vdd
    DIRECTION INOUT ;
    USE POWER ;
    SHAPE ABUTMENT ;
    PORT
      LAYER li1 ;
        RECT 1.195 5.030 1.525 5.200 ;
        RECT 3.355 5.030 3.685 5.200 ;
        RECT 1.275 5.200 1.445 6.035 ;
        RECT 3.435 5.200 3.605 6.035 ;
        RECT 0.000 6.035 3.960 6.205 ;
      LAYER met1 ;
        RECT 0.000 5.985 3.960 6.255 ;
    END
  END vdd
  PIN vss
    DIRECTION INOUT ;
    USE GROUND ;
    SHAPE ABUTMENT ;
    PORT
      LAYER li1 ;
        RECT 0.000 -0.085 3.960 0.085 ;
        RECT 1.275 0.085 1.445 0.920 ;
        RECT 1.195 0.920 1.525 1.090 ;
      LAYER met1 ;
        RECT 0.000 -0.135 3.960 0.135 ;
    END
  END vss
  PIN z
    DIRECTION OUTPUT ;
    USE SIGNAL ;
    ANTENNADIFFAREA 1.098000 ;
    PORT
      LAYER li1 ;
        RECT 0.115 1.330 0.445 1.500 ;
        RECT 0.195 1.500 0.365 4.220 ;
        RECT 0.115 4.220 0.445 4.390 ;
    END
  END z
  OBS
    LAYER li1 ;
      RECT 2.895 0.920 3.685 1.090 ;
      RECT 2.895 1.090 3.065 1.330 ;
      RECT 1.815 1.330 3.065 1.500 ;
      RECT 1.815 1.500 1.985 1.980 ;
      RECT 2.355 1.500 2.525 4.220 ;
      RECT 0.655 1.980 1.985 2.150 ;
      RECT 2.275 4.220 2.605 4.390 ;
  END
END sky130f_AN2D1

MACRO sky130f_AN2D4
  CLASS CORE ;
  FOREIGN sky130f_AN2D4 ;
  ORIGIN 0.000 0.000 ;
  SIZE 9.360 BY 6.120 ;
  SYMMETRY X Y R90 ;
  SITE obssite ;
  PIN a1
    DIRECTION INPUT ;
    USE SIGNAL ;
    ANTENNAGATEAREA 0.540000 ;
    PORT
      LAYER li1 ;
        RECT 6.675 2.520 7.465 2.690 ;
    END
  END a1
  PIN a2
    DIRECTION INPUT ;
    USE SIGNAL ;
    ANTENNAGATEAREA 0.540000 ;
    PORT
      LAYER li1 ;
        RECT 4.975 1.980 8.005 2.150 ;
    END
  END a2
  PIN vdd
    DIRECTION INOUT ;
    USE POWER ;
    SHAPE ABUTMENT ;
    PORT
      LAYER li1 ;
        RECT 0.115 5.030 0.445 5.200 ;
        RECT 2.275 5.030 2.605 5.200 ;
        RECT 4.435 5.030 4.765 5.200 ;
        RECT 6.595 5.030 6.925 5.200 ;
        RECT 8.755 5.030 9.085 5.200 ;
        RECT 0.195 5.200 0.365 6.035 ;
        RECT 2.355 5.200 2.525 6.035 ;
        RECT 4.515 5.200 4.685 6.035 ;
        RECT 6.675 5.200 6.845 6.035 ;
        RECT 8.835 5.200 9.005 6.035 ;
        RECT 0.000 6.035 9.360 6.205 ;
      LAYER met1 ;
        RECT 0.000 5.985 9.360 6.255 ;
    END
  END vdd
  PIN vss
    DIRECTION INOUT ;
    USE GROUND ;
    SHAPE ABUTMENT ;
    PORT
      LAYER li1 ;
        RECT 0.000 -0.085 9.360 0.085 ;
        RECT 0.195 0.085 0.365 0.920 ;
        RECT 2.355 0.085 2.525 0.920 ;
        RECT 4.515 0.085 4.685 0.920 ;
        RECT 8.835 0.085 9.005 0.920 ;
        RECT 0.115 0.920 0.445 1.090 ;
        RECT 2.275 0.920 2.605 1.090 ;
        RECT 4.435 0.920 4.765 1.090 ;
        RECT 8.755 0.920 9.085 1.090 ;
      LAYER met1 ;
        RECT 0.000 -0.135 9.360 0.135 ;
    END
  END vss
  PIN z
    DIRECTION OUTPUT ;
    USE SIGNAL ;
    ANTENNADIFFAREA 3.348000 ;
    PORT
      LAYER li1 ;
        RECT 1.195 1.330 1.985 1.500 ;
        RECT 3.355 1.330 3.685 1.500 ;
        RECT 1.275 1.500 1.445 4.220 ;
        RECT 1.815 1.500 1.985 1.980 ;
        RECT 3.435 1.500 3.605 1.980 ;
        RECT 1.815 1.980 3.605 2.150 ;
        RECT 3.435 2.150 3.605 4.220 ;
        RECT 1.195 4.220 1.525 4.390 ;
        RECT 3.355 4.220 3.685 4.390 ;
    END
  END z
  OBS
    LAYER li1 ;
      RECT 4.975 0.270 6.305 0.440 ;
      RECT 6.135 0.440 6.305 0.920 ;
      RECT 6.135 0.920 6.925 1.090 ;
      RECT 4.435 3.060 7.925 3.230 ;
      RECT 5.595 3.230 5.765 4.220 ;
      RECT 7.755 3.230 7.925 4.220 ;
      RECT 5.515 4.220 5.845 4.390 ;
      RECT 7.675 4.220 8.005 4.390 ;
  END
END sky130f_AN2D4

MACRO sky130f_OR2D1
  CLASS CORE ;
  FOREIGN sky130f_OR2D1 ;
  ORIGIN 0.000 0.000 ;
  SIZE 3.960 BY 6.120 ;
  SYMMETRY X Y R90 ;
  SITE obssite ;
  PIN a1
    DIRECTION INPUT ;
    USE SIGNAL ;
    ANTENNAGATEAREA 0.260250 ;
    PORT
      LAYER li1 ;
        RECT 2.815 1.980 3.145 2.150 ;
        RECT 2.895 2.150 3.065 2.690 ;
    END
  END a1
  PIN a2
    DIRECTION INPUT ;
    USE SIGNAL ;
    ANTENNAGATEAREA 0.260250 ;
    PORT
      LAYER li1 ;
        RECT 1.735 2.520 2.065 2.690 ;
        RECT 1.815 2.690 1.985 3.230 ;
    END
  END a2
  PIN vdd
    DIRECTION INOUT ;
    USE POWER ;
    SHAPE ABUTMENT ;
    PORT
      LAYER li1 ;
        RECT 1.195 5.030 1.525 5.200 ;
        RECT 1.275 5.200 1.445 6.035 ;
        RECT 0.000 6.035 3.960 6.205 ;
      LAYER met1 ;
        RECT 0.000 5.985 3.960 6.255 ;
    END
  END vdd
  PIN vss
    DIRECTION INOUT ;
    USE GROUND ;
    SHAPE ABUTMENT ;
    PORT
      LAYER li1 ;
        RECT 0.000 -0.085 3.960 0.085 ;
        RECT 1.275 0.085 1.445 0.920 ;
        RECT 3.435 0.085 3.605 0.920 ;
        RECT 1.195 0.920 1.525 1.090 ;
        RECT 3.355 0.920 3.685 1.090 ;
      LAYER met1 ;
        RECT 0.000 -0.135 3.960 0.135 ;
    END
  END vss
  PIN z
    DIRECTION OUTPUT ;
    USE SIGNAL ;
    ANTENNADIFFAREA 1.058350 ;
    PORT
      LAYER li1 ;
        RECT 0.115 0.920 0.445 1.090 ;
        RECT 0.195 1.090 0.365 4.220 ;
        RECT 0.115 4.220 0.445 4.390 ;
    END
  END z
  OBS
    LAYER li1 ;
      RECT 2.275 0.920 2.605 1.090 ;
      RECT 2.355 1.090 2.525 1.980 ;
      RECT 1.195 1.980 2.525 2.150 ;
      RECT 2.355 2.150 2.525 3.060 ;
      RECT 2.355 3.060 3.605 3.230 ;
      RECT 3.435 3.230 3.605 4.220 ;
      RECT 3.355 4.220 3.685 4.390 ;
  END
END sky130f_OR2D1

MACRO sky130f_AO21D1
  CLASS CORE ;
  FOREIGN sky130f_AO21D1 ;
  ORIGIN 0.000 0.000 ;
  SIZE 5.040 BY 6.120 ;
  SYMMETRY X Y R90 ;
  SITE obssite ;
  PIN a1
    DIRECTION INPUT ;
    USE SIGNAL ;
    ANTENNAGATEAREA 0.270000 ;
    PORT
      LAYER li1 ;
        RECT 1.735 1.980 2.065 2.150 ;
        RECT 1.815 2.150 1.985 2.690 ;
    END
  END a1
  PIN a2
    DIRECTION INPUT ;
    USE SIGNAL ;
    ANTENNAGATEAREA 0.270000 ;
    PORT
      LAYER li1 ;
        RECT 0.655 1.980 0.985 2.150 ;
        RECT 0.735 2.150 0.905 2.690 ;
    END
  END a2
  PIN b
    DIRECTION INPUT ;
    USE SIGNAL ;
    ANTENNAGATEAREA 0.270000 ;
    PORT
      LAYER li1 ;
        RECT 2.815 2.520 3.145 2.690 ;
        RECT 2.895 2.690 3.065 3.230 ;
    END
  END b
  PIN vdd
    DIRECTION INOUT ;
    USE POWER ;
    SHAPE ABUTMENT ;
    PORT
      LAYER li1 ;
        RECT 3.355 5.030 3.685 5.200 ;
        RECT 3.435 5.200 3.605 6.035 ;
        RECT 0.000 6.035 5.040 6.205 ;
      LAYER met1 ;
        RECT 0.000 5.985 5.040 6.255 ;
    END
  END vdd
  PIN vss
    DIRECTION INOUT ;
    USE GROUND ;
    SHAPE ABUTMENT ;
    PORT
      LAYER li1 ;
        RECT 0.000 -0.085 5.040 0.085 ;
        RECT 0.195 0.085 0.365 0.920 ;
        RECT 3.435 0.085 3.605 0.920 ;
        RECT 0.115 0.920 0.445 1.090 ;
        RECT 3.355 0.920 3.685 1.090 ;
      LAYER met1 ;
        RECT 0.000 -0.135 5.040 0.135 ;
    END
  END vss
  PIN z
    DIRECTION OUTPUT ;
    USE SIGNAL ;
    ANTENNADIFFAREA 1.098000 ;
    PORT
      LAYER li1 ;
        RECT 4.435 1.330 4.765 1.500 ;
        RECT 4.515 1.500 4.685 4.220 ;
        RECT 4.435 4.220 4.765 4.390 ;
    END
  END z
  OBS
    LAYER li1 ;
      RECT 2.275 1.330 2.605 1.500 ;
      RECT 2.355 1.500 2.525 1.980 ;
      RECT 2.355 1.980 4.225 2.150 ;
      RECT 2.355 2.150 2.525 3.060 ;
      RECT 1.275 3.060 2.525 3.230 ;
      RECT 1.275 3.230 1.445 4.220 ;
      RECT 1.195 4.220 1.525 4.390 ;
      RECT 0.115 5.030 0.905 5.200 ;
      RECT 1.815 5.030 2.605 5.200 ;
      RECT 0.735 5.200 0.905 5.680 ;
      RECT 1.815 5.200 1.985 5.680 ;
      RECT 0.735 5.680 1.985 5.850 ;
  END
END sky130f_AO21D1

MACRO sky130f_OA21D1
  CLASS CORE ;
  FOREIGN sky130f_OA21D1 ;
  ORIGIN 0.000 0.000 ;
  SIZE 5.040 BY 6.120 ;
  SYMMETRY X Y R90 ;
  SITE obssite ;
  PIN a1
    DIRECTION INPUT ;
    USE SIGNAL ;
    ANTENNAGATEAREA 0.270000 ;
    PORT
      LAYER li1 ;
        RECT 2.815 2.520 3.145 2.690 ;
        RECT 2.895 2.690 3.065 3.230 ;
    END
  END a1
  PIN a2
    DIRECTION INPUT ;
    USE SIGNAL ;
    ANTENNAGATEAREA 0.270000 ;
    PORT
      LAYER li1 ;
        RECT 3.895 1.980 4.225 2.150 ;
        RECT 3.975 2.150 4.145 2.690 ;
    END
  END a2
  PIN b
    DIRECTION INPUT ;
    USE SIGNAL ;
    ANTENNAGATEAREA 0.270000 ;
    PORT
      LAYER li1 ;
        RECT 1.735 2.520 2.065 2.690 ;
        RECT 1.815 2.690 1.985 3.230 ;
    END
  END b
  PIN vdd
    DIRECTION INOUT ;
    USE POWER ;
    SHAPE ABUTMENT ;
    PORT
      LAYER li1 ;
        RECT 1.195 5.030 1.525 5.200 ;
        RECT 4.435 5.030 4.765 5.200 ;
        RECT 1.275 5.200 1.445 6.035 ;
        RECT 4.515 5.200 4.685 6.035 ;
        RECT 0.000 6.035 5.040 6.205 ;
      LAYER met1 ;
        RECT 0.000 5.985 5.040 6.255 ;
    END
  END vdd
  PIN vss
    DIRECTION INOUT ;
    USE GROUND ;
    SHAPE ABUTMENT ;
    PORT
      LAYER li1 ;
        RECT 0.000 -0.085 5.040 0.085 ;
        RECT 1.275 0.085 1.445 0.920 ;
        RECT 1.195 0.920 1.525 1.090 ;
      LAYER met1 ;
        RECT 0.000 -0.135 5.040 0.135 ;
    END
  END vss
  PIN z
    DIRECTION OUTPUT ;
    USE SIGNAL ;
    ANTENNADIFFAREA 1.098000 ;
    PORT
      LAYER li1 ;
        RECT 0.115 1.330 0.445 1.500 ;
        RECT 0.195 1.500 0.365 4.220 ;
        RECT 0.115 4.220 0.445 4.390 ;
    END
  END z
  OBS
    LAYER li1 ;
      RECT 2.895 0.270 4.145 0.440 ;
      RECT 2.895 0.440 3.065 0.920 ;
      RECT 3.975 0.440 4.145 0.920 ;
      RECT 2.275 0.920 3.065 1.090 ;
      RECT 3.975 0.920 4.765 1.090 ;
      RECT 2.895 1.330 3.685 1.500 ;
      RECT 2.895 1.500 3.065 1.980 ;
      RECT 0.655 1.980 3.065 2.150 ;
      RECT 2.355 2.150 2.525 4.220 ;
      RECT 2.275 4.220 2.605 4.390 ;
  END
END sky130f_OA21D1

MACRO sky130f_AOI21D1
  CLASS CORE ;
  FOREIGN sky130f_AOI21D1 ;
  ORIGIN 0.000 0.000 ;
  SIZE 3.960 BY 6.120 ;
  SYMMETRY X Y R90 ;
  SITE obssite ;
  PIN a1
    DIRECTION INPUT ;
    USE SIGNAL ;
    ANTENNAGATEAREA 0.270000 ;
    PORT
      LAYER li1 ;
        RECT 1.735 1.980 2.065 2.150 ;
        RECT 1.815 2.150 1.985 2.690 ;
    END
  END a1
  PIN a2
    DIRECTION INPUT ;
    USE SIGNAL ;
    ANTENNAGATEAREA 0.270000 ;
    PORT
      LAYER li1 ;
        RECT 2.815 1.980 3.145 2.150 ;
        RECT 2.895 2.150 3.065 2.690 ;
    END
  END a2
  PIN b
    DIRECTION INPUT ;
    USE SIGNAL ;
    ANTENNAGATEAREA 0.270000 ;
    PORT
      LAYER li1 ;
        RECT 0.655 1.980 0.985 2.150 ;
        RECT 0.735 2.150 0.905 2.690 ;
    END
  END b
  PIN vdd
    DIRECTION INOUT ;
    USE POWER ;
    SHAPE ABUTMENT ;
    PORT
      LAYER li1 ;
        RECT 0.115 5.030 0.445 5.200 ;
        RECT 0.195 5.200 0.365 6.035 ;
        RECT 0.000 6.035 3.960 6.205 ;
      LAYER met1 ;
        RECT 0.000 5.985 3.960 6.255 ;
    END
  END vdd
  PIN vss
    DIRECTION INOUT ;
    USE GROUND ;
    SHAPE ABUTMENT ;
    PORT
      LAYER li1 ;
        RECT 0.000 -0.085 3.960 0.085 ;
        RECT 0.195 0.085 0.365 0.920 ;
        RECT 3.435 0.085 3.605 0.920 ;
        RECT 0.115 0.920 0.445 1.090 ;
        RECT 3.355 0.920 3.685 1.090 ;
      LAYER met1 ;
        RECT 0.000 -0.135 3.960 0.135 ;
    END
  END vss
  PIN zn
    DIRECTION OUTPUT ;
    USE SIGNAL ;
    ANTENNADIFFAREA 1.674000 ;
    PORT
      LAYER li1 ;
        RECT 1.195 1.330 1.525 1.500 ;
        RECT 1.275 1.500 1.445 3.060 ;
        RECT 1.275 3.060 2.525 3.230 ;
        RECT 2.355 3.230 2.525 4.220 ;
        RECT 2.275 4.220 2.605 4.390 ;
    END
  END zn
  OBS
    LAYER li1 ;
      RECT 1.195 5.030 1.985 5.200 ;
      RECT 2.895 5.030 3.685 5.200 ;
      RECT 1.815 5.200 1.985 5.680 ;
      RECT 2.895 5.200 3.065 5.680 ;
      RECT 1.815 5.680 3.065 5.850 ;
  END
END sky130f_AOI21D1

MACRO sky130f_OAI21D1
  CLASS CORE ;
  FOREIGN sky130f_OAI21D1 ;
  ORIGIN 0.000 0.000 ;
  SIZE 3.960 BY 6.120 ;
  SYMMETRY X Y R90 ;
  SITE obssite ;
  PIN a1
    DIRECTION INPUT ;
    USE SIGNAL ;
    ANTENNAGATEAREA 0.270000 ;
    PORT
      LAYER li1 ;
        RECT 1.735 1.980 2.065 2.150 ;
        RECT 1.815 2.150 1.985 2.690 ;
    END
  END a1
  PIN a2
    DIRECTION INPUT ;
    USE SIGNAL ;
    ANTENNAGATEAREA 0.270000 ;
    PORT
      LAYER li1 ;
        RECT 0.655 1.980 0.985 2.150 ;
        RECT 0.735 2.150 0.905 2.690 ;
    END
  END a2
  PIN b
    DIRECTION INPUT ;
    USE SIGNAL ;
    ANTENNAGATEAREA 0.270000 ;
    PORT
      LAYER li1 ;
        RECT 2.815 1.980 3.145 2.150 ;
        RECT 2.895 2.150 3.065 2.690 ;
    END
  END b
  PIN vdd
    DIRECTION INOUT ;
    USE POWER ;
    SHAPE ABUTMENT ;
    PORT
      LAYER li1 ;
        RECT 0.115 5.030 0.445 5.200 ;
        RECT 3.355 5.030 3.685 5.200 ;
        RECT 0.195 5.200 0.365 6.035 ;
        RECT 3.435 5.200 3.605 6.035 ;
        RECT 0.000 6.035 3.960 6.205 ;
      LAYER met1 ;
        RECT 0.000 5.985 3.960 6.255 ;
    END
  END vdd
  PIN vss
    DIRECTION INOUT ;
    USE GROUND ;
    SHAPE ABUTMENT ;
    PORT
      LAYER li1 ;
        RECT 0.000 -0.085 3.960 0.085 ;
        RECT 3.435 0.085 3.605 0.920 ;
        RECT 3.355 0.920 3.685 1.090 ;
      LAYER met1 ;
        RECT 0.000 -0.135 3.960 0.135 ;
    END
  END vss
  PIN zn
    DIRECTION OUTPUT ;
    USE SIGNAL ;
    ANTENNADIFFAREA 1.674000 ;
    PORT
      LAYER li1 ;
        RECT 1.195 1.330 1.525 1.500 ;
        RECT 1.275 1.500 1.445 3.060 ;
        RECT 1.275 3.060 2.525 3.230 ;
        RECT 2.355 3.230 2.525 4.220 ;
        RECT 2.275 4.220 2.605 4.390 ;
    END
  END zn
  OBS
    LAYER li1 ;
      RECT 0.735 0.270 1.985 0.440 ;
      RECT 0.735 0.440 0.905 0.920 ;
      RECT 1.815 0.440 1.985 0.920 ;
      RECT 0.115 0.920 0.905 1.090 ;
      RECT 1.815 0.920 2.605 1.090 ;
  END
END sky130f_OAI21D1

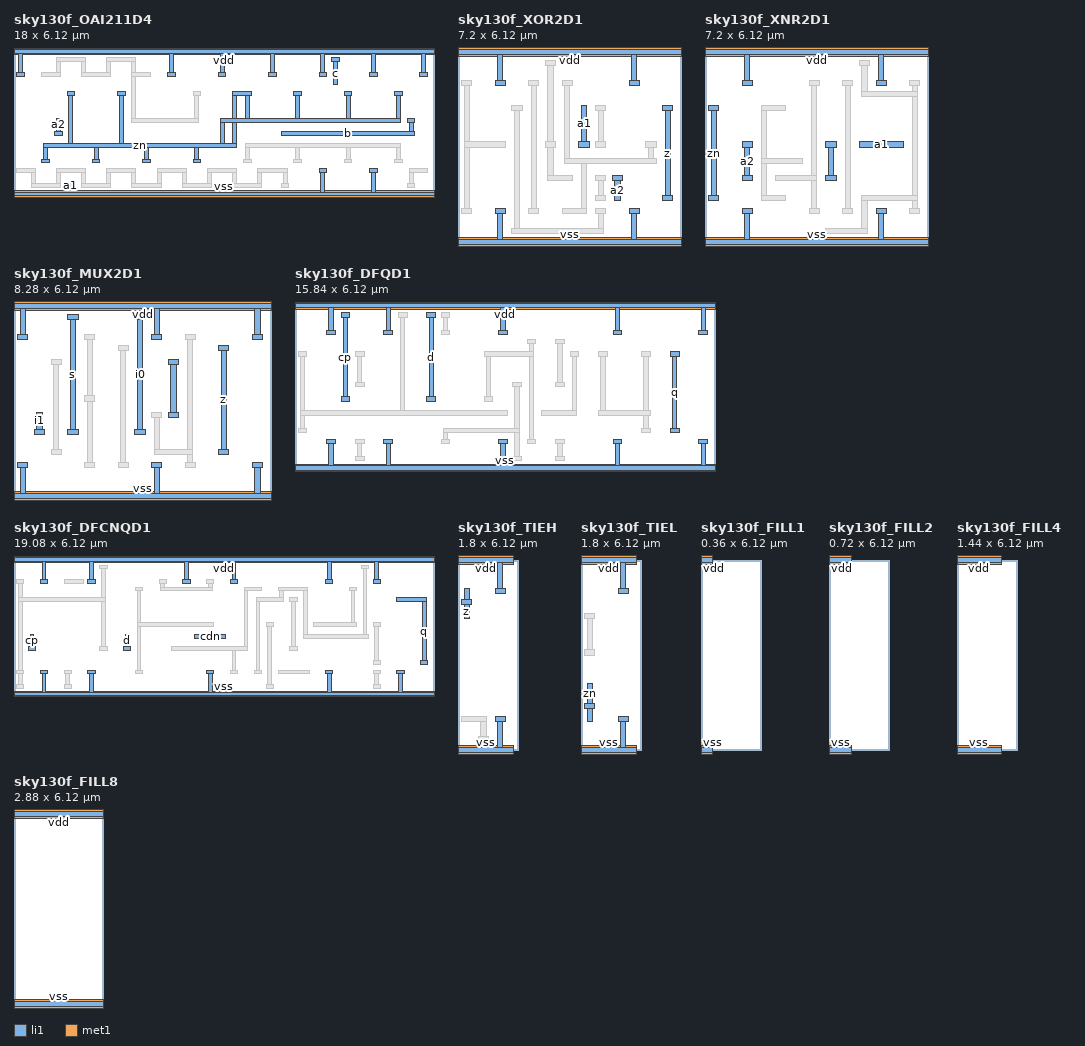
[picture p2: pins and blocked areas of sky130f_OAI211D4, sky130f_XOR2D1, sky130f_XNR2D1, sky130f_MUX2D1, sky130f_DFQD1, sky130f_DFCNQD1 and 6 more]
MACRO sky130f_OAI211D4
  CLASS CORE ;
  FOREIGN sky130f_OAI211D4 ;
  ORIGIN 0.000 0.000 ;
  SIZE 18.000 BY 6.120 ;
  SYMMETRY X Y R90 ;
  SITE obssite ;
  PIN a1
    DIRECTION INPUT ;
    USE SIGNAL ;
    ANTENNAGATEAREA 1.080000 ;
    PORT
      LAYER li1 ;
        RECT 2.275 0.270 2.605 0.440 ;
    END
  END a1
  PIN a2
    DIRECTION INPUT ;
    USE SIGNAL ;
    ANTENNAGATEAREA 1.080000 ;
    PORT
      LAYER li1 ;
        RECT 1.735 2.520 2.065 2.690 ;
        RECT 1.815 2.690 1.985 3.230 ;
    END
  END a2
  PIN b
    DIRECTION INPUT ;
    USE SIGNAL ;
    ANTENNAGATEAREA 1.080000 ;
    PORT
      LAYER li1 ;
        RECT 11.455 2.520 17.185 2.690 ;
        RECT 16.935 2.690 17.105 3.060 ;
        RECT 16.855 3.060 17.185 3.230 ;
    END
  END b
  PIN c
    DIRECTION INPUT ;
    USE SIGNAL ;
    ANTENNAGATEAREA 1.080000 ;
    PORT
      LAYER li1 ;
        RECT 13.695 4.690 13.865 5.680 ;
        RECT 13.615 5.680 13.945 5.850 ;
    END
  END c
  PIN vdd
    DIRECTION INOUT ;
    USE POWER ;
    SHAPE ABUTMENT ;
    PORT
      LAYER li1 ;
        RECT 0.115 5.030 0.445 5.200 ;
        RECT 6.595 5.030 6.925 5.200 ;
        RECT 8.755 5.030 9.085 5.200 ;
        RECT 10.915 5.030 11.245 5.200 ;
        RECT 13.075 5.030 13.405 5.200 ;
        RECT 15.235 5.030 15.565 5.200 ;
        RECT 17.395 5.030 17.725 5.200 ;
        RECT 0.195 5.200 0.365 6.035 ;
        RECT 6.675 5.200 6.845 6.035 ;
        RECT 8.835 5.200 9.005 6.035 ;
        RECT 10.995 5.200 11.165 6.035 ;
        RECT 13.155 5.200 13.325 6.035 ;
        RECT 15.315 5.200 15.485 6.035 ;
        RECT 17.475 5.200 17.645 6.035 ;
        RECT 0.000 6.035 18.000 6.205 ;
      LAYER met1 ;
        RECT 0.000 5.985 18.000 6.255 ;
    END
  END vdd
  PIN vss
    DIRECTION INOUT ;
    USE GROUND ;
    SHAPE ABUTMENT ;
    PORT
      LAYER li1 ;
        RECT 0.000 -0.085 18.000 0.085 ;
        RECT 13.155 0.085 13.325 0.920 ;
        RECT 15.315 0.085 15.485 0.920 ;
        RECT 13.075 0.920 13.405 1.090 ;
        RECT 15.235 0.920 15.565 1.090 ;
      LAYER met1 ;
        RECT 0.000 -0.135 18.000 0.135 ;
    END
  END vss
  PIN zn
    DIRECTION OUTPUT ;
    USE SIGNAL ;
    ANTENNADIFFAREA 8.742000 ;
    PORT
      LAYER li1 ;
        RECT 1.195 1.330 1.525 1.500 ;
        RECT 3.355 1.330 3.685 1.500 ;
        RECT 5.515 1.330 5.845 1.500 ;
        RECT 7.675 1.330 8.005 1.500 ;
        RECT 1.275 1.500 1.445 1.980 ;
        RECT 3.435 1.500 3.605 1.980 ;
        RECT 5.595 1.500 5.765 1.980 ;
        RECT 7.755 1.500 7.925 1.980 ;
        RECT 1.275 1.980 9.545 2.150 ;
        RECT 2.355 2.150 2.525 4.220 ;
        RECT 4.515 2.150 4.685 4.220 ;
        RECT 8.835 2.150 9.005 3.060 ;
        RECT 9.375 2.150 9.545 3.060 ;
        RECT 8.835 3.060 16.565 3.230 ;
        RECT 9.375 3.230 9.545 4.220 ;
        RECT 9.915 3.230 10.085 4.220 ;
        RECT 12.075 3.230 12.245 4.220 ;
        RECT 14.235 3.230 14.405 4.220 ;
        RECT 16.395 3.230 16.565 4.220 ;
        RECT 2.275 4.220 2.605 4.390 ;
        RECT 4.435 4.220 4.765 4.390 ;
        RECT 9.375 4.220 10.165 4.390 ;
        RECT 11.995 4.220 12.325 4.390 ;
        RECT 14.155 4.220 14.485 4.390 ;
        RECT 16.315 4.220 16.645 4.390 ;
    END
  END zn
  OBS
    LAYER li1 ;
      RECT 0.735 0.270 1.985 0.440 ;
      RECT 2.895 0.270 4.145 0.440 ;
      RECT 5.055 0.270 6.305 0.440 ;
      RECT 7.215 0.270 8.465 0.440 ;
      RECT 9.375 0.270 10.625 0.440 ;
      RECT 11.455 0.270 11.785 0.440 ;
      RECT 16.855 0.270 17.185 0.440 ;
      RECT 0.735 0.440 0.905 0.920 ;
      RECT 1.815 0.440 1.985 0.920 ;
      RECT 2.895 0.440 3.065 0.920 ;
      RECT 3.975 0.440 4.145 0.920 ;
      RECT 5.055 0.440 5.225 0.920 ;
      RECT 6.135 0.440 6.305 0.920 ;
      RECT 7.215 0.440 7.385 0.920 ;
      RECT 8.295 0.440 8.465 0.920 ;
      RECT 9.375 0.440 9.545 0.920 ;
      RECT 10.455 0.440 10.625 0.920 ;
      RECT 11.535 0.440 11.705 0.920 ;
      RECT 16.935 0.440 17.105 0.920 ;
      RECT 0.115 0.920 0.905 1.090 ;
      RECT 1.815 0.920 3.065 1.090 ;
      RECT 3.975 0.920 5.225 1.090 ;
      RECT 6.135 0.920 7.385 1.090 ;
      RECT 8.295 0.920 9.545 1.090 ;
      RECT 10.455 0.920 11.705 1.090 ;
      RECT 16.935 0.920 17.725 1.090 ;
      RECT 9.835 1.330 10.165 1.500 ;
      RECT 11.995 1.330 12.325 1.500 ;
      RECT 14.155 1.330 14.485 1.500 ;
      RECT 16.315 1.330 16.645 1.500 ;
      RECT 9.915 1.500 10.085 1.980 ;
      RECT 12.075 1.500 12.245 1.980 ;
      RECT 14.235 1.500 14.405 1.980 ;
      RECT 16.395 1.500 16.565 1.980 ;
      RECT 9.915 1.980 16.565 2.150 ;
      RECT 5.055 3.060 7.925 3.230 ;
      RECT 5.055 3.230 5.225 5.030 ;
      RECT 7.755 3.230 7.925 4.220 ;
      RECT 7.675 4.220 8.005 4.390 ;
      RECT 1.195 5.030 1.985 5.200 ;
      RECT 2.895 5.030 4.145 5.200 ;
      RECT 5.055 5.030 5.845 5.200 ;
      RECT 1.815 5.200 1.985 5.680 ;
      RECT 2.895 5.200 3.065 5.680 ;
      RECT 3.975 5.200 4.145 5.680 ;
      RECT 5.055 5.200 5.225 5.680 ;
      RECT 1.815 5.680 3.065 5.850 ;
      RECT 3.975 5.680 5.225 5.850 ;
  END
END sky130f_OAI211D4

MACRO sky130f_XOR2D1
  CLASS CORE ;
  FOREIGN sky130f_XOR2D1 ;
  ORIGIN 0.000 0.000 ;
  SIZE 7.200 BY 6.120 ;
  SYMMETRY X Y R90 ;
  SITE obssite ;
  PIN a1
    DIRECTION INPUT ;
    USE SIGNAL ;
    ANTENNAGATEAREA 0.291000 ;
    PORT
      LAYER li1 ;
        RECT 3.895 3.060 4.225 3.230 ;
        RECT 3.975 3.230 4.145 4.390 ;
    END
  END a1
  PIN a2
    DIRECTION INPUT ;
    USE SIGNAL ;
    ANTENNAGATEAREA 0.270000 ;
    PORT
      LAYER li1 ;
        RECT 5.055 1.330 5.225 1.980 ;
        RECT 4.975 1.980 5.305 2.150 ;
    END
  END a2
  PIN vdd
    DIRECTION INOUT ;
    USE POWER ;
    SHAPE ABUTMENT ;
    PORT
      LAYER li1 ;
        RECT 1.195 5.030 1.525 5.200 ;
        RECT 5.515 5.030 5.845 5.200 ;
        RECT 1.275 5.200 1.445 6.035 ;
        RECT 5.595 5.200 5.765 6.035 ;
        RECT 0.000 6.035 7.200 6.205 ;
      LAYER met1 ;
        RECT 0.000 5.985 7.200 6.255 ;
    END
  END vdd
  PIN vss
    DIRECTION INOUT ;
    USE GROUND ;
    SHAPE ABUTMENT ;
    PORT
      LAYER li1 ;
        RECT 0.000 -0.085 7.200 0.085 ;
        RECT 1.275 0.085 1.445 0.920 ;
        RECT 5.595 0.085 5.765 0.920 ;
        RECT 1.195 0.920 1.525 1.090 ;
        RECT 5.515 0.920 5.845 1.090 ;
      LAYER met1 ;
        RECT 0.000 -0.135 7.200 0.135 ;
    END
  END vss
  PIN z
    DIRECTION OUTPUT ;
    USE SIGNAL ;
    ANTENNADIFFAREA 1.098000 ;
    PORT
      LAYER li1 ;
        RECT 6.595 1.330 6.925 1.500 ;
        RECT 6.675 1.500 6.845 4.220 ;
        RECT 6.595 4.220 6.925 4.390 ;
    END
  END z
  OBS
    LAYER li1 ;
      RECT 1.735 0.270 4.685 0.440 ;
      RECT 1.815 0.440 1.985 4.220 ;
      RECT 4.515 0.440 4.685 0.920 ;
      RECT 0.115 0.920 0.445 1.090 ;
      RECT 2.275 0.920 2.605 1.090 ;
      RECT 3.355 0.920 4.145 1.090 ;
      RECT 4.435 0.920 4.765 1.090 ;
      RECT 0.195 1.090 0.365 3.060 ;
      RECT 2.355 1.090 2.525 5.030 ;
      RECT 3.975 1.090 4.145 2.520 ;
      RECT 4.435 1.330 4.765 1.500 ;
      RECT 4.515 1.500 4.685 1.980 ;
      RECT 2.895 1.980 3.685 2.150 ;
      RECT 4.435 1.980 4.765 2.150 ;
      RECT 2.895 2.150 3.065 3.060 ;
      RECT 3.435 2.520 6.385 2.690 ;
      RECT 3.435 2.690 3.605 5.030 ;
      RECT 6.135 2.690 6.305 3.060 ;
      RECT 0.195 3.060 1.525 3.230 ;
      RECT 2.815 3.060 3.145 3.230 ;
      RECT 4.435 3.060 4.765 3.230 ;
      RECT 6.055 3.060 6.385 3.230 ;
      RECT 0.195 3.230 0.365 5.030 ;
      RECT 2.895 3.230 3.065 5.680 ;
      RECT 4.515 3.230 4.685 4.220 ;
      RECT 1.735 4.220 2.065 4.390 ;
      RECT 4.435 4.220 4.765 4.390 ;
      RECT 0.115 5.030 0.445 5.200 ;
      RECT 2.275 5.030 2.605 5.200 ;
      RECT 3.355 5.030 3.685 5.200 ;
      RECT 2.815 5.680 3.145 5.850 ;
  END
END sky130f_XOR2D1

MACRO sky130f_XNR2D1
  CLASS CORE ;
  FOREIGN sky130f_XNR2D1 ;
  ORIGIN 0.000 0.000 ;
  SIZE 7.200 BY 6.120 ;
  SYMMETRY X Y R90 ;
  SITE obssite ;
  PIN a1
    DIRECTION INPUT ;
    USE SIGNAL ;
    ANTENNAGATEAREA 0.291000 ;
    PORT
      LAYER li1 ;
        RECT 3.895 1.980 4.225 2.150 ;
        RECT 3.975 2.150 4.145 3.060 ;
        RECT 3.895 3.060 4.225 3.230 ;
        RECT 4.975 3.060 6.385 3.230 ;
    END
  END a1
  PIN a2
    DIRECTION INPUT ;
    USE SIGNAL ;
    ANTENNAGATEAREA 0.270000 ;
    PORT
      LAYER li1 ;
        RECT 1.195 1.980 1.525 2.150 ;
        RECT 1.275 2.150 1.445 3.060 ;
        RECT 1.195 3.060 1.525 3.230 ;
    END
  END a2
  PIN vdd
    DIRECTION INOUT ;
    USE POWER ;
    SHAPE ABUTMENT ;
    PORT
      LAYER li1 ;
        RECT 1.195 5.030 1.525 5.200 ;
        RECT 5.515 5.030 5.845 5.200 ;
        RECT 1.275 5.200 1.445 6.035 ;
        RECT 5.595 5.200 5.765 6.035 ;
        RECT 0.000 6.035 7.200 6.205 ;
      LAYER met1 ;
        RECT 0.000 5.985 7.200 6.255 ;
    END
  END vdd
  PIN vss
    DIRECTION INOUT ;
    USE GROUND ;
    SHAPE ABUTMENT ;
    PORT
      LAYER li1 ;
        RECT 0.000 -0.085 7.200 0.085 ;
        RECT 1.275 0.085 1.445 0.920 ;
        RECT 5.595 0.085 5.765 0.920 ;
        RECT 1.195 0.920 1.525 1.090 ;
        RECT 5.515 0.920 5.845 1.090 ;
      LAYER met1 ;
        RECT 0.000 -0.135 7.200 0.135 ;
    END
  END vss
  PIN zn
    DIRECTION OUTPUT ;
    USE SIGNAL ;
    ANTENNADIFFAREA 1.098000 ;
    PORT
      LAYER li1 ;
        RECT 0.115 1.330 0.445 1.500 ;
        RECT 0.195 1.500 0.365 4.220 ;
        RECT 0.115 4.220 0.445 4.390 ;
    END
  END zn
  OBS
    LAYER li1 ;
      RECT 3.895 0.270 5.225 0.440 ;
      RECT 5.055 0.440 5.225 1.330 ;
      RECT 3.355 0.920 3.685 1.090 ;
      RECT 4.435 0.920 4.765 1.090 ;
      RECT 6.595 0.920 6.925 1.090 ;
      RECT 3.435 1.090 3.605 1.980 ;
      RECT 4.515 1.090 4.685 5.030 ;
      RECT 6.675 1.090 6.845 1.330 ;
      RECT 1.815 1.330 2.605 1.500 ;
      RECT 5.055 1.330 6.845 1.500 ;
      RECT 1.815 1.500 1.985 2.520 ;
      RECT 6.675 1.500 6.845 4.690 ;
      RECT 2.275 1.980 3.605 2.150 ;
      RECT 3.435 2.150 3.605 5.030 ;
      RECT 1.815 2.520 3.145 2.690 ;
      RECT 1.815 2.690 1.985 4.220 ;
      RECT 1.815 4.220 2.605 4.390 ;
      RECT 5.055 4.690 6.845 4.860 ;
      RECT 5.055 4.860 5.225 5.680 ;
      RECT 6.675 4.860 6.845 5.030 ;
      RECT 3.355 5.030 3.685 5.200 ;
      RECT 4.435 5.030 4.765 5.200 ;
      RECT 6.595 5.030 6.925 5.200 ;
      RECT 4.975 5.680 5.305 5.850 ;
  END
END sky130f_XNR2D1

MACRO sky130f_MUX2D1
  CLASS CORE ;
  FOREIGN sky130f_MUX2D1 ;
  ORIGIN 0.000 0.000 ;
  SIZE 8.280 BY 6.120 ;
  SYMMETRY X Y R90 ;
  SITE obssite ;
  PIN i0
    DIRECTION INPUT ;
    USE SIGNAL ;
    ANTENNAGATEAREA 0.212250 ;
    PORT
      LAYER li1 ;
        RECT 3.895 1.980 4.225 2.150 ;
        RECT 3.975 2.150 4.145 5.680 ;
        RECT 3.895 5.680 4.225 5.850 ;
    END
  END i0
  PIN i1
    DIRECTION INPUT ;
    USE SIGNAL ;
    ANTENNAGATEAREA 0.270000 ;
    PORT
      LAYER li1 ;
        RECT 0.655 1.980 0.985 2.150 ;
        RECT 0.735 2.150 0.905 2.690 ;
    END
  END i1
  PIN s
    DIRECTION INPUT ;
    USE SIGNAL ;
    ANTENNAGATEAREA 0.291000 ;
    PORT
      LAYER li1 ;
        RECT 1.735 1.980 2.065 2.150 ;
        RECT 1.815 2.150 1.985 5.680 ;
        RECT 4.975 2.520 5.305 2.690 ;
        RECT 5.055 2.690 5.225 4.220 ;
        RECT 4.975 4.220 5.305 4.390 ;
        RECT 1.735 5.680 2.065 5.850 ;
    END
  END s
  PIN vdd
    DIRECTION INOUT ;
    USE POWER ;
    SHAPE ABUTMENT ;
    PORT
      LAYER li1 ;
        RECT 0.115 5.030 0.445 5.200 ;
        RECT 4.435 5.030 4.765 5.200 ;
        RECT 7.675 5.030 8.005 5.200 ;
        RECT 0.195 5.200 0.365 6.035 ;
        RECT 4.515 5.200 4.685 6.035 ;
        RECT 7.755 5.200 7.925 6.035 ;
        RECT 0.000 6.035 8.280 6.205 ;
      LAYER met1 ;
        RECT 0.000 5.985 8.280 6.255 ;
    END
  END vdd
  PIN vss
    DIRECTION INOUT ;
    USE GROUND ;
    SHAPE ABUTMENT ;
    PORT
      LAYER li1 ;
        RECT 0.000 -0.085 8.280 0.085 ;
        RECT 0.195 0.085 0.365 0.920 ;
        RECT 4.515 0.085 4.685 0.920 ;
        RECT 7.755 0.085 7.925 0.920 ;
        RECT 0.115 0.920 0.445 1.090 ;
        RECT 4.435 0.920 4.765 1.090 ;
        RECT 7.675 0.920 8.005 1.090 ;
      LAYER met1 ;
        RECT 0.000 -0.135 8.280 0.135 ;
    END
  END vss
  PIN z
    DIRECTION OUTPUT ;
    USE SIGNAL ;
    ANTENNADIFFAREA 0.896700 ;
    PORT
      LAYER li1 ;
        RECT 6.595 1.330 6.925 1.500 ;
        RECT 6.675 1.500 6.845 4.690 ;
        RECT 6.595 4.690 6.925 4.860 ;
    END
  END z
  OBS
    LAYER li1 ;
      RECT 2.275 0.920 2.605 1.090 ;
      RECT 3.355 0.920 3.685 1.090 ;
      RECT 5.515 0.920 5.845 1.090 ;
      RECT 2.355 1.090 2.525 3.060 ;
      RECT 3.435 1.090 3.605 4.690 ;
      RECT 5.595 1.090 5.765 1.330 ;
      RECT 1.195 1.330 1.525 1.500 ;
      RECT 4.515 1.330 5.765 1.500 ;
      RECT 1.275 1.500 1.445 4.220 ;
      RECT 4.515 1.500 4.685 2.520 ;
      RECT 5.595 1.500 5.765 5.030 ;
      RECT 4.435 2.520 4.765 2.690 ;
      RECT 2.275 3.060 2.605 3.230 ;
      RECT 2.355 3.230 2.525 5.030 ;
      RECT 1.195 4.220 1.525 4.390 ;
      RECT 3.355 4.690 3.685 4.860 ;
      RECT 2.275 5.030 2.605 5.200 ;
      RECT 5.515 5.030 5.845 5.200 ;
  END
END sky130f_MUX2D1

MACRO sky130f_DFQD1
  CLASS CORE ;
  FOREIGN sky130f_DFQD1 ;
  ORIGIN 0.000 0.000 ;
  SIZE 15.840 BY 6.120 ;
  SYMMETRY X Y R90 ;
  SITE obssite ;
  PIN cp
    DIRECTION INPUT ;
    USE SIGNAL ;
    ANTENNAGATEAREA 0.270000 ;
    PORT
      LAYER li1 ;
        RECT 1.735 2.520 2.065 2.690 ;
        RECT 1.815 2.690 1.985 5.680 ;
        RECT 1.735 5.680 2.065 5.850 ;
    END
  END cp
  PIN d
    DIRECTION INPUT ;
    USE SIGNAL ;
    ANTENNAGATEAREA 0.166500 ;
    PORT
      LAYER li1 ;
        RECT 4.975 2.520 5.305 2.690 ;
        RECT 5.055 2.690 5.225 5.680 ;
        RECT 4.975 5.680 5.305 5.850 ;
    END
  END d
  PIN q
    DIRECTION OUTPUT ;
    USE SIGNAL ;
    ANTENNADIFFAREA 1.098000 ;
    PORT
      LAYER li1 ;
        RECT 14.155 1.330 14.485 1.500 ;
        RECT 14.235 1.500 14.405 4.220 ;
        RECT 14.155 4.220 14.485 4.390 ;
    END
  END q
  PIN vdd
    DIRECTION INOUT ;
    USE POWER ;
    SHAPE ABUTMENT ;
    PORT
      LAYER li1 ;
        RECT 1.195 5.030 1.525 5.200 ;
        RECT 3.355 5.030 3.685 5.200 ;
        RECT 7.675 5.030 8.005 5.200 ;
        RECT 11.995 5.030 12.325 5.200 ;
        RECT 15.235 5.030 15.565 5.200 ;
        RECT 1.275 5.200 1.445 6.035 ;
        RECT 3.435 5.200 3.605 6.035 ;
        RECT 7.755 5.200 7.925 6.035 ;
        RECT 12.075 5.200 12.245 6.035 ;
        RECT 15.315 5.200 15.485 6.035 ;
        RECT 0.000 6.035 15.840 6.205 ;
      LAYER met1 ;
        RECT 0.000 5.985 15.840 6.255 ;
    END
  END vdd
  PIN vss
    DIRECTION INOUT ;
    USE GROUND ;
    SHAPE ABUTMENT ;
    PORT
      LAYER li1 ;
        RECT 0.000 -0.085 15.840 0.085 ;
        RECT 1.275 0.085 1.445 0.920 ;
        RECT 3.435 0.085 3.605 0.920 ;
        RECT 7.755 0.085 7.925 0.920 ;
        RECT 12.075 0.085 12.245 0.920 ;
        RECT 15.315 0.085 15.485 0.920 ;
        RECT 1.195 0.920 1.525 1.090 ;
        RECT 3.355 0.920 3.685 1.090 ;
        RECT 7.675 0.920 8.005 1.090 ;
        RECT 11.995 0.920 12.325 1.090 ;
        RECT 15.235 0.920 15.565 1.090 ;
      LAYER met1 ;
        RECT 0.000 -0.135 15.840 0.135 ;
    END
  END vss
  OBS
    LAYER li1 ;
      RECT 2.275 0.270 2.605 0.440 ;
      RECT 8.215 0.270 8.545 0.440 ;
      RECT 9.835 0.270 10.165 0.440 ;
      RECT 2.355 0.440 2.525 0.920 ;
      RECT 8.295 0.440 8.465 1.330 ;
      RECT 9.915 0.440 10.085 0.920 ;
      RECT 2.275 0.920 2.605 1.090 ;
      RECT 5.515 0.920 5.845 1.090 ;
      RECT 8.755 0.920 9.085 1.090 ;
      RECT 9.835 0.920 10.165 1.090 ;
      RECT 5.595 1.090 5.765 1.330 ;
      RECT 8.835 1.090 9.005 4.220 ;
      RECT 0.115 1.330 0.445 1.500 ;
      RECT 5.595 1.330 8.465 1.500 ;
      RECT 13.075 1.330 13.405 1.500 ;
      RECT 0.195 1.500 0.365 1.980 ;
      RECT 8.295 1.500 8.465 3.060 ;
      RECT 13.155 1.500 13.325 1.980 ;
      RECT 0.195 1.980 8.005 2.150 ;
      RECT 9.295 1.980 10.625 2.150 ;
      RECT 11.455 1.980 13.405 2.150 ;
      RECT 0.195 2.150 0.365 4.220 ;
      RECT 3.975 2.150 4.145 5.680 ;
      RECT 10.455 2.150 10.625 4.220 ;
      RECT 11.535 2.150 11.705 4.220 ;
      RECT 13.155 2.150 13.325 4.220 ;
      RECT 7.135 2.520 7.465 2.690 ;
      RECT 7.215 2.690 7.385 4.220 ;
      RECT 2.275 3.060 2.605 3.230 ;
      RECT 8.215 3.060 8.545 3.230 ;
      RECT 9.835 3.060 10.165 3.230 ;
      RECT 2.355 3.230 2.525 4.220 ;
      RECT 9.915 3.230 10.085 4.690 ;
      RECT 0.115 4.220 0.445 4.390 ;
      RECT 2.275 4.220 2.605 4.390 ;
      RECT 7.135 4.220 9.005 4.390 ;
      RECT 10.375 4.220 10.705 4.390 ;
      RECT 11.455 4.220 11.785 4.390 ;
      RECT 13.075 4.220 13.405 4.390 ;
      RECT 8.835 4.390 9.005 4.690 ;
      RECT 8.755 4.690 9.085 4.860 ;
      RECT 9.835 4.690 10.165 4.860 ;
      RECT 5.515 5.030 5.845 5.200 ;
      RECT 5.595 5.200 5.765 5.680 ;
      RECT 3.895 5.680 4.225 5.850 ;
      RECT 5.515 5.680 5.845 5.850 ;
  END
END sky130f_DFQD1

MACRO sky130f_DFCNQD1
  CLASS CORE ;
  FOREIGN sky130f_DFCNQD1 ;
  ORIGIN 0.000 0.000 ;
  SIZE 19.080 BY 6.120 ;
  SYMMETRY X Y R90 ;
  SITE obssite ;
  PIN cdn
    DIRECTION INPUT ;
    USE SIGNAL ;
    ANTENNAGATEAREA 0.379500 ;
    PORT
      LAYER li1 ;
        RECT 8.215 2.520 9.625 2.690 ;
    END
  END cdn
  PIN cp
    DIRECTION INPUT ;
    USE SIGNAL ;
    ANTENNAGATEAREA 0.145500 ;
    PORT
      LAYER li1 ;
        RECT 0.655 1.980 0.985 2.150 ;
        RECT 0.735 2.150 0.905 2.690 ;
    END
  END cp
  PIN d
    DIRECTION INPUT ;
    USE SIGNAL ;
    ANTENNAGATEAREA 0.184500 ;
    PORT
      LAYER li1 ;
        RECT 4.975 1.980 5.305 2.150 ;
        RECT 5.055 2.150 5.225 2.690 ;
    END
  END d
  PIN q
    DIRECTION OUTPUT ;
    USE SIGNAL ;
    ANTENNADIFFAREA 1.098000 ;
    PORT
      LAYER li1 ;
        RECT 18.475 1.330 18.805 1.500 ;
        RECT 18.555 1.500 18.725 4.220 ;
        RECT 17.395 4.220 18.725 4.390 ;
    END
  END q
  PIN vdd
    DIRECTION INOUT ;
    USE POWER ;
    SHAPE ABUTMENT ;
    PORT
      LAYER li1 ;
        RECT 1.195 5.030 1.525 5.200 ;
        RECT 3.355 5.030 3.685 5.200 ;
        RECT 7.675 5.030 8.005 5.200 ;
        RECT 9.835 5.030 10.165 5.200 ;
        RECT 14.155 5.030 14.485 5.200 ;
        RECT 16.315 5.030 16.645 5.200 ;
        RECT 1.275 5.200 1.445 6.035 ;
        RECT 3.435 5.200 3.605 6.035 ;
        RECT 7.755 5.200 7.925 6.035 ;
        RECT 9.915 5.200 10.085 6.035 ;
        RECT 14.235 5.200 14.405 6.035 ;
        RECT 16.395 5.200 16.565 6.035 ;
        RECT 0.000 6.035 19.080 6.205 ;
      LAYER met1 ;
        RECT 0.000 5.985 19.080 6.255 ;
    END
  END vdd
  PIN vss
    DIRECTION INOUT ;
    USE GROUND ;
    SHAPE ABUTMENT ;
    PORT
      LAYER li1 ;
        RECT 0.000 -0.085 19.080 0.085 ;
        RECT 1.275 0.085 1.445 0.920 ;
        RECT 3.435 0.085 3.605 0.920 ;
        RECT 8.835 0.085 9.005 0.920 ;
        RECT 14.235 0.085 14.405 0.920 ;
        RECT 17.475 0.085 17.645 0.920 ;
        RECT 1.195 0.920 1.525 1.090 ;
        RECT 3.355 0.920 3.685 1.090 ;
        RECT 8.755 0.920 9.085 1.090 ;
        RECT 14.155 0.920 14.485 1.090 ;
        RECT 17.395 0.920 17.725 1.090 ;
      LAYER met1 ;
        RECT 0.000 -0.135 19.080 0.135 ;
    END
  END vss
  OBS
    LAYER li1 ;
      RECT 0.115 0.270 0.445 0.440 ;
      RECT 2.275 0.270 2.605 0.440 ;
      RECT 11.455 0.270 11.785 0.440 ;
      RECT 16.315 0.270 16.645 0.440 ;
      RECT 0.195 0.440 0.365 0.920 ;
      RECT 2.355 0.440 2.525 0.920 ;
      RECT 11.535 0.440 11.705 3.060 ;
      RECT 16.395 0.440 16.565 0.920 ;
      RECT 0.115 0.920 0.445 1.090 ;
      RECT 2.275 0.920 2.605 1.090 ;
      RECT 5.515 0.920 5.845 1.090 ;
      RECT 9.835 0.920 10.165 1.090 ;
      RECT 10.915 0.920 11.245 1.090 ;
      RECT 11.995 0.920 13.405 1.090 ;
      RECT 16.315 0.920 16.645 1.090 ;
      RECT 0.195 1.090 0.365 4.220 ;
      RECT 5.595 1.090 5.765 3.060 ;
      RECT 9.915 1.090 10.085 1.980 ;
      RECT 10.995 1.090 11.165 4.220 ;
      RECT 16.315 1.330 16.645 1.500 ;
      RECT 16.395 1.500 16.565 3.060 ;
      RECT 3.895 1.980 4.225 2.150 ;
      RECT 7.135 1.980 10.625 2.150 ;
      RECT 12.535 1.980 12.865 2.150 ;
      RECT 3.975 2.150 4.145 4.220 ;
      RECT 10.455 2.150 10.625 4.690 ;
      RECT 12.615 2.150 12.785 4.220 ;
      RECT 13.155 2.520 16.105 2.690 ;
      RECT 13.155 2.690 13.325 4.690 ;
      RECT 15.855 2.690 16.025 5.680 ;
      RECT 5.595 3.060 9.085 3.230 ;
      RECT 11.455 3.060 11.785 3.230 ;
      RECT 13.615 3.060 15.565 3.230 ;
      RECT 16.315 3.060 16.645 3.230 ;
      RECT 5.595 3.230 5.765 4.690 ;
      RECT 15.315 3.230 15.485 4.690 ;
      RECT 0.195 4.220 4.145 4.390 ;
      RECT 10.995 4.220 12.245 4.390 ;
      RECT 12.535 4.220 12.865 4.390 ;
      RECT 0.195 4.390 0.365 5.030 ;
      RECT 3.975 4.390 4.145 5.680 ;
      RECT 12.075 4.390 12.245 4.690 ;
      RECT 5.515 4.690 5.845 4.860 ;
      RECT 6.675 4.690 9.005 4.860 ;
      RECT 10.455 4.690 11.245 4.860 ;
      RECT 11.995 4.690 13.325 4.860 ;
      RECT 15.235 4.690 15.565 4.860 ;
      RECT 6.675 4.860 6.845 5.030 ;
      RECT 8.835 4.860 9.005 5.030 ;
      RECT 0.115 5.030 0.445 5.200 ;
      RECT 2.275 5.030 3.145 5.200 ;
      RECT 6.595 5.030 6.925 5.200 ;
      RECT 8.755 5.030 9.085 5.200 ;
      RECT 3.895 5.680 4.225 5.850 ;
      RECT 15.775 5.680 16.105 5.850 ;
  END
END sky130f_DFCNQD1

MACRO sky130f_TIEH
  CLASS CORE TIEHIGH ;
  FOREIGN sky130f_TIEH ;
  ORIGIN 0.000 0.000 ;
  SIZE 1.800 BY 6.120 ;
  SYMMETRY X Y R90 ;
  SITE obssite ;
  PIN vdd
    DIRECTION INOUT ;
    USE POWER ;
    SHAPE ABUTMENT ;
    PORT
      LAYER li1 ;
        RECT 1.195 5.030 1.525 5.200 ;
        RECT 1.275 5.200 1.445 6.035 ;
        RECT 0.000 6.035 1.800 6.205 ;
      LAYER met1 ;
        RECT 0.000 5.985 1.800 6.255 ;
    END
  END vdd
  PIN vss
    DIRECTION INOUT ;
    USE GROUND ;
    SHAPE ABUTMENT ;
    PORT
      LAYER li1 ;
        RECT 0.000 -0.085 1.800 0.085 ;
        RECT 1.275 0.085 1.445 0.920 ;
        RECT 1.195 0.920 1.525 1.090 ;
      LAYER met1 ;
        RECT 0.000 -0.135 1.800 0.135 ;
    END
  END vss
  PIN z
    DIRECTION OUTPUT ;
    USE SIGNAL ;
    ANTENNADIFFAREA 0.671000 ;
    PORT
      LAYER li1 ;
        RECT 0.195 4.220 0.365 4.690 ;
        RECT 0.115 4.690 0.445 4.860 ;
        RECT 0.195 4.860 0.365 5.200 ;
    END
  END z
  OBS
    LAYER li1 ;
      RECT 0.655 0.270 0.985 0.440 ;
      RECT 0.735 0.440 0.905 0.920 ;
      RECT 0.115 0.920 0.905 1.090 ;
  END
END sky130f_TIEH

MACRO sky130f_TIEL
  CLASS CORE TIELOW ;
  FOREIGN sky130f_TIEL ;
  ORIGIN 0.000 0.000 ;
  SIZE 1.800 BY 6.120 ;
  SYMMETRY X Y R90 ;
  SITE obssite ;
  PIN vdd
    DIRECTION INOUT ;
    USE POWER ;
    SHAPE ABUTMENT ;
    PORT
      LAYER li1 ;
        RECT 1.195 5.030 1.525 5.200 ;
        RECT 1.275 5.200 1.445 6.035 ;
        RECT 0.000 6.035 1.800 6.205 ;
      LAYER met1 ;
        RECT 0.000 5.985 1.800 6.255 ;
    END
  END vdd
  PIN vss
    DIRECTION INOUT ;
    USE GROUND ;
    SHAPE ABUTMENT ;
    PORT
      LAYER li1 ;
        RECT 0.000 -0.085 1.800 0.085 ;
        RECT 1.275 0.085 1.445 0.920 ;
        RECT 1.195 0.920 1.525 1.090 ;
      LAYER met1 ;
        RECT 0.000 -0.135 1.800 0.135 ;
    END
  END vss
  PIN zn
    DIRECTION OUTPUT ;
    USE SIGNAL ;
    ANTENNADIFFAREA 0.427000 ;
    PORT
      LAYER li1 ;
        RECT 0.195 0.920 0.365 1.330 ;
        RECT 0.115 1.330 0.445 1.500 ;
        RECT 0.195 1.500 0.365 2.150 ;
    END
  END zn
  OBS
    LAYER li1 ;
      RECT 0.115 3.060 0.445 3.230 ;
      RECT 0.195 3.230 0.365 4.220 ;
      RECT 0.115 4.220 0.445 4.390 ;
  END
END sky130f_TIEL

MACRO sky130f_FILL1
  CLASS CORE SPACER ;
  FOREIGN sky130f_FILL1 ;
  ORIGIN 0.000 0.000 ;
  SIZE 0.360 BY 6.120 ;
  SYMMETRY X Y R90 ;
  SITE obssite ;
  PIN vdd
    DIRECTION INOUT ;
    USE POWER ;
    SHAPE ABUTMENT ;
    PORT
      LAYER li1 ;
        RECT 0.000 6.035 0.360 6.205 ;
      LAYER met1 ;
        RECT 0.000 5.985 0.360 6.255 ;
    END
  END vdd
  PIN vss
    DIRECTION INOUT ;
    USE GROUND ;
    SHAPE ABUTMENT ;
    PORT
      LAYER li1 ;
        RECT 0.000 -0.085 0.360 0.085 ;
      LAYER met1 ;
        RECT 0.000 -0.135 0.360 0.135 ;
    END
  END vss
END sky130f_FILL1

MACRO sky130f_FILL2
  CLASS CORE SPACER ;
  FOREIGN sky130f_FILL2 ;
  ORIGIN 0.000 0.000 ;
  SIZE 0.720 BY 6.120 ;
  SYMMETRY X Y R90 ;
  SITE obssite ;
  PIN vdd
    DIRECTION INOUT ;
    USE POWER ;
    SHAPE ABUTMENT ;
    PORT
      LAYER li1 ;
        RECT 0.000 6.035 0.720 6.205 ;
      LAYER met1 ;
        RECT 0.000 5.985 0.720 6.255 ;
    END
  END vdd
  PIN vss
    DIRECTION INOUT ;
    USE GROUND ;
    SHAPE ABUTMENT ;
    PORT
      LAYER li1 ;
        RECT 0.000 -0.085 0.720 0.085 ;
      LAYER met1 ;
        RECT 0.000 -0.135 0.720 0.135 ;
    END
  END vss
END sky130f_FILL2

MACRO sky130f_FILL4
  CLASS CORE SPACER ;
  FOREIGN sky130f_FILL4 ;
  ORIGIN 0.000 0.000 ;
  SIZE 1.440 BY 6.120 ;
  SYMMETRY X Y R90 ;
  SITE obssite ;
  PIN vdd
    DIRECTION INOUT ;
    USE POWER ;
    SHAPE ABUTMENT ;
    PORT
      LAYER li1 ;
        RECT 0.000 6.035 1.440 6.205 ;
      LAYER met1 ;
        RECT 0.000 5.985 1.440 6.255 ;
    END
  END vdd
  PIN vss
    DIRECTION INOUT ;
    USE GROUND ;
    SHAPE ABUTMENT ;
    PORT
      LAYER li1 ;
        RECT 0.000 -0.085 1.440 0.085 ;
      LAYER met1 ;
        RECT 0.000 -0.135 1.440 0.135 ;
    END
  END vss
END sky130f_FILL4

MACRO sky130f_FILL8
  CLASS CORE SPACER ;
  FOREIGN sky130f_FILL8 ;
  ORIGIN 0.000 0.000 ;
  SIZE 2.880 BY 6.120 ;
  SYMMETRY X Y R90 ;
  SITE obssite ;
  PIN vdd
    DIRECTION INOUT ;
    USE POWER ;
    SHAPE ABUTMENT ;
    PORT
      LAYER li1 ;
        RECT 0.000 6.035 2.880 6.205 ;
      LAYER met1 ;
        RECT 0.000 5.985 2.880 6.255 ;
    END
  END vdd
  PIN vss
    DIRECTION INOUT ;
    USE GROUND ;
    SHAPE ABUTMENT ;
    PORT
      LAYER li1 ;
        RECT 0.000 -0.085 2.880 0.085 ;
      LAYER met1 ;
        RECT 0.000 -0.135 2.880 0.135 ;
    END
  END vss
END sky130f_FILL8

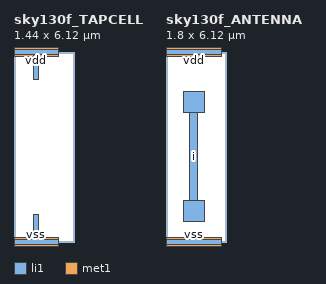
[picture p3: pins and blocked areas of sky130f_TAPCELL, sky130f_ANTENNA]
MACRO sky130f_TAPCELL
  CLASS CORE WELLTAP ;
  FOREIGN sky130f_TAPCELL ;
  ORIGIN 0.000 0.000 ;
  SIZE 1.440 BY 6.120 ;
  SYMMETRY X Y R90 ;
  SITE obssite ;
  PIN vdd
    DIRECTION INOUT ;
    USE POWER ;
    SHAPE ABUTMENT ;
    PORT
      LAYER li1 ;
        RECT 0.635 5.235 0.805 6.035 ;
        RECT 0.000 6.035 1.440 6.205 ;
      LAYER met1 ;
        RECT 0.000 5.985 1.440 6.255 ;
    END
  END vdd
  PIN vss
    DIRECTION INOUT ;
    USE GROUND ;
    SHAPE ABUTMENT ;
    PORT
      LAYER li1 ;
        RECT 0.000 -0.085 1.440 0.085 ;
        RECT 0.635 0.085 0.805 0.885 ;
      LAYER met1 ;
        RECT 0.000 -0.135 1.440 0.135 ;
    END
  END vss
END sky130f_TAPCELL

MACRO sky130f_ANTENNA
  CLASS CORE ANTENNACELL ;
  FOREIGN sky130f_ANTENNA ;
  ORIGIN 0.000 0.000 ;
  SIZE 1.800 BY 6.120 ;
  SYMMETRY X Y R90 ;
  SITE obssite ;
  PIN i
    DIRECTION INPUT ;
    USE SIGNAL ;
    PORT
      LAYER li1 ;
        RECT 0.565 0.665 1.235 1.335 ;
        RECT 0.770 1.335 1.030 4.165 ;
        RECT 0.565 4.165 1.235 4.835 ;
    END
  END i
  PIN vdd
    DIRECTION INOUT ;
    USE POWER ;
    SHAPE ABUTMENT ;
    PORT
      LAYER li1 ;
        RECT 0.000 6.035 1.800 6.205 ;
      LAYER met1 ;
        RECT 0.000 5.985 1.800 6.255 ;
    END
  END vdd
  PIN vss
    DIRECTION INOUT ;
    USE GROUND ;
    SHAPE ABUTMENT ;
    PORT
      LAYER li1 ;
        RECT 0.000 -0.085 1.800 0.085 ;
      LAYER met1 ;
        RECT 0.000 -0.135 1.800 0.135 ;
    END
  END vss
END sky130f_ANTENNA

END LIBRARY
